VERSION 5.8 ;
BUSBITCHARS "[]" ;
DIVIDERCHAR "/" ;
UNITS
    DATABASE MICRONS 1000 ;
END UNITS

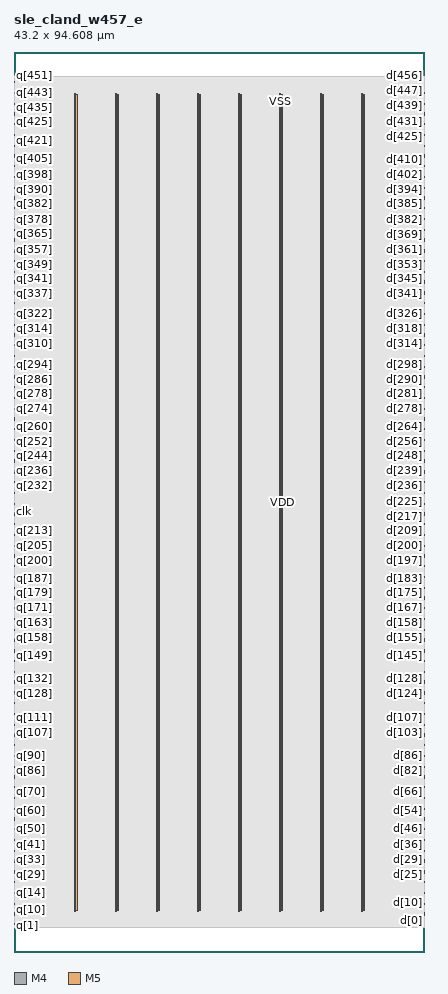
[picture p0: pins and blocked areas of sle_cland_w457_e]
MACRO sle_cland_w457_e
  FOREIGN sle_cland_w457_e 0 0 ;
  CLASS BLOCK ;
  SIZE 43.2 BY 94.608 ;
  PIN clk
    DIRECTION INPUT ;
    USE SIGNAL ;
    PORT
      LAYER M4 ;
        RECT  0 46.32 0.084 46.344 ;
    END
  END clk
  PIN d[0]
    DIRECTION INPUT ;
    USE SIGNAL ;
    PORT
      LAYER M4 ;
        RECT  43.116 3.312 43.2 3.336 ;
    END
  END d[0]
  PIN d[100]
    DIRECTION INPUT ;
    USE SIGNAL ;
    PORT
      LAYER M4 ;
        RECT  43.116 22.512 43.2 22.536 ;
    END
  END d[100]
  PIN d[101]
    DIRECTION INPUT ;
    USE SIGNAL ;
    PORT
      LAYER M4 ;
        RECT  43.116 22.704 43.2 22.728 ;
    END
  END d[101]
  PIN d[102]
    DIRECTION INPUT ;
    USE SIGNAL ;
    PORT
      LAYER M4 ;
        RECT  43.116 22.896 43.2 22.92 ;
    END
  END d[102]
  PIN d[103]
    DIRECTION INPUT ;
    USE SIGNAL ;
    PORT
      LAYER M4 ;
        RECT  43.116 23.088 43.2 23.112 ;
    END
  END d[103]
  PIN d[104]
    DIRECTION INPUT ;
    USE SIGNAL ;
    PORT
      LAYER M4 ;
        RECT  43.116 23.28 43.2 23.304 ;
    END
  END d[104]
  PIN d[105]
    DIRECTION INPUT ;
    USE SIGNAL ;
    PORT
      LAYER M4 ;
        RECT  43.116 23.472 43.2 23.496 ;
    END
  END d[105]
  PIN d[106]
    DIRECTION INPUT ;
    USE SIGNAL ;
    PORT
      LAYER M4 ;
        RECT  43.116 23.664 43.2 23.688 ;
    END
  END d[106]
  PIN d[107]
    DIRECTION INPUT ;
    USE SIGNAL ;
    PORT
      LAYER M4 ;
        RECT  43.116 23.856 43.2 23.88 ;
    END
  END d[107]
  PIN d[108]
    DIRECTION INPUT ;
    USE SIGNAL ;
    PORT
      LAYER M4 ;
        RECT  43.116 24.048 43.2 24.072 ;
    END
  END d[108]
  PIN d[109]
    DIRECTION INPUT ;
    USE SIGNAL ;
    PORT
      LAYER M4 ;
        RECT  43.116 24.24 43.2 24.264 ;
    END
  END d[109]
  PIN d[10]
    DIRECTION INPUT ;
    USE SIGNAL ;
    PORT
      LAYER M4 ;
        RECT  43.116 5.232 43.2 5.256 ;
    END
  END d[10]
  PIN d[110]
    DIRECTION INPUT ;
    USE SIGNAL ;
    PORT
      LAYER M4 ;
        RECT  43.116 24.432 43.2 24.456 ;
    END
  END d[110]
  PIN d[111]
    DIRECTION INPUT ;
    USE SIGNAL ;
    PORT
      LAYER M4 ;
        RECT  43.116 24.624 43.2 24.648 ;
    END
  END d[111]
  PIN d[112]
    DIRECTION INPUT ;
    USE SIGNAL ;
    PORT
      LAYER M4 ;
        RECT  43.116 24.816 43.2 24.84 ;
    END
  END d[112]
  PIN d[113]
    DIRECTION INPUT ;
    USE SIGNAL ;
    PORT
      LAYER M4 ;
        RECT  43.116 25.008 43.2 25.032 ;
    END
  END d[113]
  PIN d[114]
    DIRECTION INPUT ;
    USE SIGNAL ;
    PORT
      LAYER M4 ;
        RECT  43.116 25.2 43.2 25.224 ;
    END
  END d[114]
  PIN d[115]
    DIRECTION INPUT ;
    USE SIGNAL ;
    PORT
      LAYER M4 ;
        RECT  43.116 25.584 43.2 25.608 ;
    END
  END d[115]
  PIN d[116]
    DIRECTION INPUT ;
    USE SIGNAL ;
    PORT
      LAYER M4 ;
        RECT  43.116 25.392 43.2 25.416 ;
    END
  END d[116]
  PIN d[117]
    DIRECTION INPUT ;
    USE SIGNAL ;
    PORT
      LAYER M4 ;
        RECT  43.116 25.776 43.2 25.8 ;
    END
  END d[117]
  PIN d[118]
    DIRECTION INPUT ;
    USE SIGNAL ;
    PORT
      LAYER M4 ;
        RECT  43.116 26.16 43.2 26.184 ;
    END
  END d[118]
  PIN d[119]
    DIRECTION INPUT ;
    USE SIGNAL ;
    PORT
      LAYER M4 ;
        RECT  43.116 25.968 43.2 25.992 ;
    END
  END d[119]
  PIN d[11]
    DIRECTION INPUT ;
    USE SIGNAL ;
    PORT
      LAYER M4 ;
        RECT  43.116 5.424 43.2 5.448 ;
    END
  END d[11]
  PIN d[120]
    DIRECTION INPUT ;
    USE SIGNAL ;
    PORT
      LAYER M4 ;
        RECT  43.116 26.352 43.2 26.376 ;
    END
  END d[120]
  PIN d[121]
    DIRECTION INPUT ;
    USE SIGNAL ;
    PORT
      LAYER M4 ;
        RECT  43.116 26.544 43.2 26.568 ;
    END
  END d[121]
  PIN d[122]
    DIRECTION INPUT ;
    USE SIGNAL ;
    PORT
      LAYER M4 ;
        RECT  43.116 26.736 43.2 26.76 ;
    END
  END d[122]
  PIN d[123]
    DIRECTION INPUT ;
    USE SIGNAL ;
    PORT
      LAYER M4 ;
        RECT  43.116 26.928 43.2 26.952 ;
    END
  END d[123]
  PIN d[124]
    DIRECTION INPUT ;
    USE SIGNAL ;
    PORT
      LAYER M4 ;
        RECT  43.116 27.12 43.2 27.144 ;
    END
  END d[124]
  PIN d[125]
    DIRECTION INPUT ;
    USE SIGNAL ;
    PORT
      LAYER M4 ;
        RECT  43.116 27.312 43.2 27.336 ;
    END
  END d[125]
  PIN d[126]
    DIRECTION INPUT ;
    USE SIGNAL ;
    PORT
      LAYER M4 ;
        RECT  43.116 27.504 43.2 27.528 ;
    END
  END d[126]
  PIN d[127]
    DIRECTION INPUT ;
    USE SIGNAL ;
    PORT
      LAYER M4 ;
        RECT  43.116 27.696 43.2 27.72 ;
    END
  END d[127]
  PIN d[128]
    DIRECTION INPUT ;
    USE SIGNAL ;
    PORT
      LAYER M4 ;
        RECT  43.116 27.888 43.2 27.912 ;
    END
  END d[128]
  PIN d[129]
    DIRECTION INPUT ;
    USE SIGNAL ;
    PORT
      LAYER M4 ;
        RECT  43.116 28.08 43.2 28.104 ;
    END
  END d[129]
  PIN d[12]
    DIRECTION INPUT ;
    USE SIGNAL ;
    PORT
      LAYER M4 ;
        RECT  43.116 5.616 43.2 5.64 ;
    END
  END d[12]
  PIN d[130]
    DIRECTION INPUT ;
    USE SIGNAL ;
    PORT
      LAYER M4 ;
        RECT  43.116 28.272 43.2 28.296 ;
    END
  END d[130]
  PIN d[131]
    DIRECTION INPUT ;
    USE SIGNAL ;
    PORT
      LAYER M4 ;
        RECT  43.116 28.464 43.2 28.488 ;
    END
  END d[131]
  PIN d[132]
    DIRECTION INPUT ;
    USE SIGNAL ;
    PORT
      LAYER M4 ;
        RECT  43.116 28.656 43.2 28.68 ;
    END
  END d[132]
  PIN d[133]
    DIRECTION INPUT ;
    USE SIGNAL ;
    PORT
      LAYER M4 ;
        RECT  43.116 28.848 43.2 28.872 ;
    END
  END d[133]
  PIN d[134]
    DIRECTION INPUT ;
    USE SIGNAL ;
    PORT
      LAYER M4 ;
        RECT  43.116 29.04 43.2 29.064 ;
    END
  END d[134]
  PIN d[135]
    DIRECTION INPUT ;
    USE SIGNAL ;
    PORT
      LAYER M4 ;
        RECT  43.116 29.232 43.2 29.256 ;
    END
  END d[135]
  PIN d[136]
    DIRECTION INPUT ;
    USE SIGNAL ;
    PORT
      LAYER M4 ;
        RECT  43.116 29.424 43.2 29.448 ;
    END
  END d[136]
  PIN d[137]
    DIRECTION INPUT ;
    USE SIGNAL ;
    PORT
      LAYER M4 ;
        RECT  43.116 29.616 43.2 29.64 ;
    END
  END d[137]
  PIN d[138]
    DIRECTION INPUT ;
    USE SIGNAL ;
    PORT
      LAYER M4 ;
        RECT  43.116 30 43.2 30.024 ;
    END
  END d[138]
  PIN d[139]
    DIRECTION INPUT ;
    USE SIGNAL ;
    PORT
      LAYER M4 ;
        RECT  43.116 29.808 43.2 29.832 ;
    END
  END d[139]
  PIN d[13]
    DIRECTION INPUT ;
    USE SIGNAL ;
    PORT
      LAYER M4 ;
        RECT  43.116 5.808 43.2 5.832 ;
    END
  END d[13]
  PIN d[140]
    DIRECTION INPUT ;
    USE SIGNAL ;
    PORT
      LAYER M4 ;
        RECT  43.116 30.192 43.2 30.216 ;
    END
  END d[140]
  PIN d[141]
    DIRECTION INPUT ;
    USE SIGNAL ;
    PORT
      LAYER M4 ;
        RECT  43.116 30.384 43.2 30.408 ;
    END
  END d[141]
  PIN d[142]
    DIRECTION INPUT ;
    USE SIGNAL ;
    PORT
      LAYER M4 ;
        RECT  43.116 30.576 43.2 30.6 ;
    END
  END d[142]
  PIN d[143]
    DIRECTION INPUT ;
    USE SIGNAL ;
    PORT
      LAYER M4 ;
        RECT  43.116 30.768 43.2 30.792 ;
    END
  END d[143]
  PIN d[144]
    DIRECTION INPUT ;
    USE SIGNAL ;
    PORT
      LAYER M4 ;
        RECT  43.116 30.96 43.2 30.984 ;
    END
  END d[144]
  PIN d[145]
    DIRECTION INPUT ;
    USE SIGNAL ;
    PORT
      LAYER M4 ;
        RECT  43.116 31.152 43.2 31.176 ;
    END
  END d[145]
  PIN d[146]
    DIRECTION INPUT ;
    USE SIGNAL ;
    PORT
      LAYER M4 ;
        RECT  43.116 31.344 43.2 31.368 ;
    END
  END d[146]
  PIN d[147]
    DIRECTION INPUT ;
    USE SIGNAL ;
    PORT
      LAYER M4 ;
        RECT  43.116 31.536 43.2 31.56 ;
    END
  END d[147]
  PIN d[148]
    DIRECTION INPUT ;
    USE SIGNAL ;
    PORT
      LAYER M4 ;
        RECT  43.116 31.728 43.2 31.752 ;
    END
  END d[148]
  PIN d[149]
    DIRECTION INPUT ;
    USE SIGNAL ;
    PORT
      LAYER M4 ;
        RECT  43.116 31.92 43.2 31.944 ;
    END
  END d[149]
  PIN d[14]
    DIRECTION INPUT ;
    USE SIGNAL ;
    PORT
      LAYER M4 ;
        RECT  43.116 6.192 43.2 6.216 ;
    END
  END d[14]
  PIN d[150]
    DIRECTION INPUT ;
    USE SIGNAL ;
    PORT
      LAYER M4 ;
        RECT  43.116 32.112 43.2 32.136 ;
    END
  END d[150]
  PIN d[151]
    DIRECTION INPUT ;
    USE SIGNAL ;
    PORT
      LAYER M4 ;
        RECT  43.116 32.304 43.2 32.328 ;
    END
  END d[151]
  PIN d[152]
    DIRECTION INPUT ;
    USE SIGNAL ;
    PORT
      LAYER M4 ;
        RECT  43.116 32.496 43.2 32.52 ;
    END
  END d[152]
  PIN d[153]
    DIRECTION INPUT ;
    USE SIGNAL ;
    PORT
      LAYER M4 ;
        RECT  43.116 32.688 43.2 32.712 ;
    END
  END d[153]
  PIN d[154]
    DIRECTION INPUT ;
    USE SIGNAL ;
    PORT
      LAYER M4 ;
        RECT  43.116 32.88 43.2 32.904 ;
    END
  END d[154]
  PIN d[155]
    DIRECTION INPUT ;
    USE SIGNAL ;
    PORT
      LAYER M4 ;
        RECT  43.116 33.072 43.2 33.096 ;
    END
  END d[155]
  PIN d[156]
    DIRECTION INPUT ;
    USE SIGNAL ;
    PORT
      LAYER M4 ;
        RECT  43.116 33.264 43.2 33.288 ;
    END
  END d[156]
  PIN d[157]
    DIRECTION INPUT ;
    USE SIGNAL ;
    PORT
      LAYER M4 ;
        RECT  43.116 33.456 43.2 33.48 ;
    END
  END d[157]
  PIN d[158]
    DIRECTION INPUT ;
    USE SIGNAL ;
    PORT
      LAYER M4 ;
        RECT  43.116 33.84 43.2 33.864 ;
    END
  END d[158]
  PIN d[159]
    DIRECTION INPUT ;
    USE SIGNAL ;
    PORT
      LAYER M4 ;
        RECT  43.116 33.648 43.2 33.672 ;
    END
  END d[159]
  PIN d[15]
    DIRECTION INPUT ;
    USE SIGNAL ;
    PORT
      LAYER M4 ;
        RECT  43.116 6 43.2 6.024 ;
    END
  END d[15]
  PIN d[160]
    DIRECTION INPUT ;
    USE SIGNAL ;
    PORT
      LAYER M4 ;
        RECT  43.116 34.224 43.2 34.248 ;
    END
  END d[160]
  PIN d[161]
    DIRECTION INPUT ;
    USE SIGNAL ;
    PORT
      LAYER M4 ;
        RECT  43.116 34.032 43.2 34.056 ;
    END
  END d[161]
  PIN d[162]
    DIRECTION INPUT ;
    USE SIGNAL ;
    PORT
      LAYER M4 ;
        RECT  43.116 34.416 43.2 34.44 ;
    END
  END d[162]
  PIN d[163]
    DIRECTION INPUT ;
    USE SIGNAL ;
    PORT
      LAYER M4 ;
        RECT  43.116 34.608 43.2 34.632 ;
    END
  END d[163]
  PIN d[164]
    DIRECTION INPUT ;
    USE SIGNAL ;
    PORT
      LAYER M4 ;
        RECT  43.116 34.8 43.2 34.824 ;
    END
  END d[164]
  PIN d[165]
    DIRECTION INPUT ;
    USE SIGNAL ;
    PORT
      LAYER M4 ;
        RECT  43.116 34.992 43.2 35.016 ;
    END
  END d[165]
  PIN d[166]
    DIRECTION INPUT ;
    USE SIGNAL ;
    PORT
      LAYER M4 ;
        RECT  43.116 35.184 43.2 35.208 ;
    END
  END d[166]
  PIN d[167]
    DIRECTION INPUT ;
    USE SIGNAL ;
    PORT
      LAYER M4 ;
        RECT  43.116 35.376 43.2 35.4 ;
    END
  END d[167]
  PIN d[168]
    DIRECTION INPUT ;
    USE SIGNAL ;
    PORT
      LAYER M4 ;
        RECT  43.116 35.568 43.2 35.592 ;
    END
  END d[168]
  PIN d[169]
    DIRECTION INPUT ;
    USE SIGNAL ;
    PORT
      LAYER M4 ;
        RECT  43.116 35.76 43.2 35.784 ;
    END
  END d[169]
  PIN d[16]
    DIRECTION INPUT ;
    USE SIGNAL ;
    PORT
      LAYER M4 ;
        RECT  43.116 6.384 43.2 6.408 ;
    END
  END d[16]
  PIN d[170]
    DIRECTION INPUT ;
    USE SIGNAL ;
    PORT
      LAYER M4 ;
        RECT  43.116 35.952 43.2 35.976 ;
    END
  END d[170]
  PIN d[171]
    DIRECTION INPUT ;
    USE SIGNAL ;
    PORT
      LAYER M4 ;
        RECT  43.116 36.144 43.2 36.168 ;
    END
  END d[171]
  PIN d[172]
    DIRECTION INPUT ;
    USE SIGNAL ;
    PORT
      LAYER M4 ;
        RECT  43.116 36.336 43.2 36.36 ;
    END
  END d[172]
  PIN d[173]
    DIRECTION INPUT ;
    USE SIGNAL ;
    PORT
      LAYER M4 ;
        RECT  43.116 36.528 43.2 36.552 ;
    END
  END d[173]
  PIN d[174]
    DIRECTION INPUT ;
    USE SIGNAL ;
    PORT
      LAYER M4 ;
        RECT  43.116 36.72 43.2 36.744 ;
    END
  END d[174]
  PIN d[175]
    DIRECTION INPUT ;
    USE SIGNAL ;
    PORT
      LAYER M4 ;
        RECT  43.116 36.912 43.2 36.936 ;
    END
  END d[175]
  PIN d[176]
    DIRECTION INPUT ;
    USE SIGNAL ;
    PORT
      LAYER M4 ;
        RECT  43.116 37.104 43.2 37.128 ;
    END
  END d[176]
  PIN d[177]
    DIRECTION INPUT ;
    USE SIGNAL ;
    PORT
      LAYER M4 ;
        RECT  43.116 37.488 43.2 37.512 ;
    END
  END d[177]
  PIN d[178]
    DIRECTION INPUT ;
    USE SIGNAL ;
    PORT
      LAYER M4 ;
        RECT  43.116 37.296 43.2 37.32 ;
    END
  END d[178]
  PIN d[179]
    DIRECTION INPUT ;
    USE SIGNAL ;
    PORT
      LAYER M4 ;
        RECT  43.116 37.68 43.2 37.704 ;
    END
  END d[179]
  PIN d[17]
    DIRECTION INPUT ;
    USE SIGNAL ;
    PORT
      LAYER M4 ;
        RECT  43.116 6.576 43.2 6.6 ;
    END
  END d[17]
  PIN d[180]
    DIRECTION INPUT ;
    USE SIGNAL ;
    PORT
      LAYER M4 ;
        RECT  43.116 38.064 43.2 38.088 ;
    END
  END d[180]
  PIN d[181]
    DIRECTION INPUT ;
    USE SIGNAL ;
    PORT
      LAYER M4 ;
        RECT  43.116 37.872 43.2 37.896 ;
    END
  END d[181]
  PIN d[182]
    DIRECTION INPUT ;
    USE SIGNAL ;
    PORT
      LAYER M4 ;
        RECT  43.116 38.256 43.2 38.28 ;
    END
  END d[182]
  PIN d[183]
    DIRECTION INPUT ;
    USE SIGNAL ;
    PORT
      LAYER M4 ;
        RECT  43.116 38.448 43.2 38.472 ;
    END
  END d[183]
  PIN d[184]
    DIRECTION INPUT ;
    USE SIGNAL ;
    PORT
      LAYER M4 ;
        RECT  43.116 38.64 43.2 38.664 ;
    END
  END d[184]
  PIN d[185]
    DIRECTION INPUT ;
    USE SIGNAL ;
    PORT
      LAYER M4 ;
        RECT  43.116 38.832 43.2 38.856 ;
    END
  END d[185]
  PIN d[186]
    DIRECTION INPUT ;
    USE SIGNAL ;
    PORT
      LAYER M4 ;
        RECT  43.116 39.024 43.2 39.048 ;
    END
  END d[186]
  PIN d[187]
    DIRECTION INPUT ;
    USE SIGNAL ;
    PORT
      LAYER M4 ;
        RECT  43.116 39.216 43.2 39.24 ;
    END
  END d[187]
  PIN d[188]
    DIRECTION INPUT ;
    USE SIGNAL ;
    PORT
      LAYER M4 ;
        RECT  43.116 39.408 43.2 39.432 ;
    END
  END d[188]
  PIN d[189]
    DIRECTION INPUT ;
    USE SIGNAL ;
    PORT
      LAYER M4 ;
        RECT  43.116 39.6 43.2 39.624 ;
    END
  END d[189]
  PIN d[18]
    DIRECTION INPUT ;
    USE SIGNAL ;
    PORT
      LAYER M4 ;
        RECT  43.116 6.768 43.2 6.792 ;
    END
  END d[18]
  PIN d[190]
    DIRECTION INPUT ;
    USE SIGNAL ;
    PORT
      LAYER M4 ;
        RECT  43.116 39.792 43.2 39.816 ;
    END
  END d[190]
  PIN d[191]
    DIRECTION INPUT ;
    USE SIGNAL ;
    PORT
      LAYER M4 ;
        RECT  43.116 39.984 43.2 40.008 ;
    END
  END d[191]
  PIN d[192]
    DIRECTION INPUT ;
    USE SIGNAL ;
    PORT
      LAYER M4 ;
        RECT  43.116 40.176 43.2 40.2 ;
    END
  END d[192]
  PIN d[193]
    DIRECTION INPUT ;
    USE SIGNAL ;
    PORT
      LAYER M4 ;
        RECT  43.116 40.368 43.2 40.392 ;
    END
  END d[193]
  PIN d[194]
    DIRECTION INPUT ;
    USE SIGNAL ;
    PORT
      LAYER M4 ;
        RECT  43.116 40.56 43.2 40.584 ;
    END
  END d[194]
  PIN d[195]
    DIRECTION INPUT ;
    USE SIGNAL ;
    PORT
      LAYER M4 ;
        RECT  43.116 40.752 43.2 40.776 ;
    END
  END d[195]
  PIN d[196]
    DIRECTION INPUT ;
    USE SIGNAL ;
    PORT
      LAYER M4 ;
        RECT  43.116 40.944 43.2 40.968 ;
    END
  END d[196]
  PIN d[197]
    DIRECTION INPUT ;
    USE SIGNAL ;
    PORT
      LAYER M4 ;
        RECT  43.116 41.136 43.2 41.16 ;
    END
  END d[197]
  PIN d[198]
    DIRECTION INPUT ;
    USE SIGNAL ;
    PORT
      LAYER M4 ;
        RECT  43.116 41.328 43.2 41.352 ;
    END
  END d[198]
  PIN d[199]
    DIRECTION INPUT ;
    USE SIGNAL ;
    PORT
      LAYER M4 ;
        RECT  43.116 41.52 43.2 41.544 ;
    END
  END d[199]
  PIN d[19]
    DIRECTION INPUT ;
    USE SIGNAL ;
    PORT
      LAYER M4 ;
        RECT  43.116 6.96 43.2 6.984 ;
    END
  END d[19]
  PIN d[1]
    DIRECTION INPUT ;
    USE SIGNAL ;
    PORT
      LAYER M4 ;
        RECT  43.116 3.504 43.2 3.528 ;
    END
  END d[1]
  PIN d[200]
    DIRECTION INPUT ;
    USE SIGNAL ;
    PORT
      LAYER M4 ;
        RECT  43.116 41.904 43.2 41.928 ;
    END
  END d[200]
  PIN d[201]
    DIRECTION INPUT ;
    USE SIGNAL ;
    PORT
      LAYER M4 ;
        RECT  43.116 41.712 43.2 41.736 ;
    END
  END d[201]
  PIN d[202]
    DIRECTION INPUT ;
    USE SIGNAL ;
    PORT
      LAYER M4 ;
        RECT  43.116 42.096 43.2 42.12 ;
    END
  END d[202]
  PIN d[203]
    DIRECTION INPUT ;
    USE SIGNAL ;
    PORT
      LAYER M4 ;
        RECT  43.116 42.288 43.2 42.312 ;
    END
  END d[203]
  PIN d[204]
    DIRECTION INPUT ;
    USE SIGNAL ;
    PORT
      LAYER M4 ;
        RECT  43.116 42.48 43.2 42.504 ;
    END
  END d[204]
  PIN d[205]
    DIRECTION INPUT ;
    USE SIGNAL ;
    PORT
      LAYER M4 ;
        RECT  43.116 42.672 43.2 42.696 ;
    END
  END d[205]
  PIN d[206]
    DIRECTION INPUT ;
    USE SIGNAL ;
    PORT
      LAYER M4 ;
        RECT  43.116 42.864 43.2 42.888 ;
    END
  END d[206]
  PIN d[207]
    DIRECTION INPUT ;
    USE SIGNAL ;
    PORT
      LAYER M4 ;
        RECT  43.116 43.056 43.2 43.08 ;
    END
  END d[207]
  PIN d[208]
    DIRECTION INPUT ;
    USE SIGNAL ;
    PORT
      LAYER M4 ;
        RECT  43.116 43.248 43.2 43.272 ;
    END
  END d[208]
  PIN d[209]
    DIRECTION INPUT ;
    USE SIGNAL ;
    PORT
      LAYER M4 ;
        RECT  43.116 43.44 43.2 43.464 ;
    END
  END d[209]
  PIN d[20]
    DIRECTION INPUT ;
    USE SIGNAL ;
    PORT
      LAYER M4 ;
        RECT  43.116 7.152 43.2 7.176 ;
    END
  END d[20]
  PIN d[210]
    DIRECTION INPUT ;
    USE SIGNAL ;
    PORT
      LAYER M4 ;
        RECT  43.116 43.632 43.2 43.656 ;
    END
  END d[210]
  PIN d[211]
    DIRECTION INPUT ;
    USE SIGNAL ;
    PORT
      LAYER M4 ;
        RECT  43.116 43.824 43.2 43.848 ;
    END
  END d[211]
  PIN d[212]
    DIRECTION INPUT ;
    USE SIGNAL ;
    PORT
      LAYER M4 ;
        RECT  43.116 44.016 43.2 44.04 ;
    END
  END d[212]
  PIN d[213]
    DIRECTION INPUT ;
    USE SIGNAL ;
    PORT
      LAYER M4 ;
        RECT  43.116 44.208 43.2 44.232 ;
    END
  END d[213]
  PIN d[214]
    DIRECTION INPUT ;
    USE SIGNAL ;
    PORT
      LAYER M4 ;
        RECT  43.116 44.4 43.2 44.424 ;
    END
  END d[214]
  PIN d[215]
    DIRECTION INPUT ;
    USE SIGNAL ;
    PORT
      LAYER M4 ;
        RECT  43.116 44.592 43.2 44.616 ;
    END
  END d[215]
  PIN d[216]
    DIRECTION INPUT ;
    USE SIGNAL ;
    PORT
      LAYER M4 ;
        RECT  43.116 44.784 43.2 44.808 ;
    END
  END d[216]
  PIN d[217]
    DIRECTION INPUT ;
    USE SIGNAL ;
    PORT
      LAYER M4 ;
        RECT  43.116 44.976 43.2 45 ;
    END
  END d[217]
  PIN d[218]
    DIRECTION INPUT ;
    USE SIGNAL ;
    PORT
      LAYER M4 ;
        RECT  43.116 45.168 43.2 45.192 ;
    END
  END d[218]
  PIN d[219]
    DIRECTION INPUT ;
    USE SIGNAL ;
    PORT
      LAYER M4 ;
        RECT  43.116 45.36 43.2 45.384 ;
    END
  END d[219]
  PIN d[21]
    DIRECTION INPUT ;
    USE SIGNAL ;
    PORT
      LAYER M4 ;
        RECT  43.116 7.344 43.2 7.368 ;
    END
  END d[21]
  PIN d[220]
    DIRECTION INPUT ;
    USE SIGNAL ;
    PORT
      LAYER M4 ;
        RECT  43.116 45.744 43.2 45.768 ;
    END
  END d[220]
  PIN d[221]
    DIRECTION INPUT ;
    USE SIGNAL ;
    PORT
      LAYER M4 ;
        RECT  43.116 45.552 43.2 45.576 ;
    END
  END d[221]
  PIN d[222]
    DIRECTION INPUT ;
    USE SIGNAL ;
    PORT
      LAYER M4 ;
        RECT  43.116 46.128 43.2 46.152 ;
    END
  END d[222]
  PIN d[223]
    DIRECTION INPUT ;
    USE SIGNAL ;
    PORT
      LAYER M4 ;
        RECT  43.116 45.936 43.2 45.96 ;
    END
  END d[223]
  PIN d[224]
    DIRECTION INPUT ;
    USE SIGNAL ;
    PORT
      LAYER M4 ;
        RECT  43.116 46.32 43.2 46.344 ;
    END
  END d[224]
  PIN d[225]
    DIRECTION INPUT ;
    USE SIGNAL ;
    PORT
      LAYER M4 ;
        RECT  43.116 46.512 43.2 46.536 ;
    END
  END d[225]
  PIN d[226]
    DIRECTION INPUT ;
    USE SIGNAL ;
    PORT
      LAYER M4 ;
        RECT  43.116 46.704 43.2 46.728 ;
    END
  END d[226]
  PIN d[227]
    DIRECTION INPUT ;
    USE SIGNAL ;
    PORT
      LAYER M4 ;
        RECT  43.116 46.896 43.2 46.92 ;
    END
  END d[227]
  PIN d[228]
    DIRECTION INPUT ;
    USE SIGNAL ;
    PORT
      LAYER M4 ;
        RECT  43.116 47.472 43.2 47.496 ;
    END
  END d[228]
  PIN d[229]
    DIRECTION INPUT ;
    USE SIGNAL ;
    PORT
      LAYER M4 ;
        RECT  43.116 47.664 43.2 47.688 ;
    END
  END d[229]
  PIN d[22]
    DIRECTION INPUT ;
    USE SIGNAL ;
    PORT
      LAYER M4 ;
        RECT  43.116 7.536 43.2 7.56 ;
    END
  END d[22]
  PIN d[230]
    DIRECTION INPUT ;
    USE SIGNAL ;
    PORT
      LAYER M4 ;
        RECT  43.116 47.856 43.2 47.88 ;
    END
  END d[230]
  PIN d[231]
    DIRECTION INPUT ;
    USE SIGNAL ;
    PORT
      LAYER M4 ;
        RECT  43.116 48.048 43.2 48.072 ;
    END
  END d[231]
  PIN d[232]
    DIRECTION INPUT ;
    USE SIGNAL ;
    PORT
      LAYER M4 ;
        RECT  43.116 48.24 43.2 48.264 ;
    END
  END d[232]
  PIN d[233]
    DIRECTION INPUT ;
    USE SIGNAL ;
    PORT
      LAYER M4 ;
        RECT  43.116 48.432 43.2 48.456 ;
    END
  END d[233]
  PIN d[234]
    DIRECTION INPUT ;
    USE SIGNAL ;
    PORT
      LAYER M4 ;
        RECT  43.116 48.624 43.2 48.648 ;
    END
  END d[234]
  PIN d[235]
    DIRECTION INPUT ;
    USE SIGNAL ;
    PORT
      LAYER M4 ;
        RECT  43.116 48.816 43.2 48.84 ;
    END
  END d[235]
  PIN d[236]
    DIRECTION INPUT ;
    USE SIGNAL ;
    PORT
      LAYER M4 ;
        RECT  43.116 49.008 43.2 49.032 ;
    END
  END d[236]
  PIN d[237]
    DIRECTION INPUT ;
    USE SIGNAL ;
    PORT
      LAYER M4 ;
        RECT  43.116 49.2 43.2 49.224 ;
    END
  END d[237]
  PIN d[238]
    DIRECTION INPUT ;
    USE SIGNAL ;
    PORT
      LAYER M4 ;
        RECT  43.116 49.392 43.2 49.416 ;
    END
  END d[238]
  PIN d[239]
    DIRECTION INPUT ;
    USE SIGNAL ;
    PORT
      LAYER M4 ;
        RECT  43.116 49.776 43.2 49.8 ;
    END
  END d[239]
  PIN d[23]
    DIRECTION INPUT ;
    USE SIGNAL ;
    PORT
      LAYER M4 ;
        RECT  43.116 7.728 43.2 7.752 ;
    END
  END d[23]
  PIN d[240]
    DIRECTION INPUT ;
    USE SIGNAL ;
    PORT
      LAYER M4 ;
        RECT  43.116 49.584 43.2 49.608 ;
    END
  END d[240]
  PIN d[241]
    DIRECTION INPUT ;
    USE SIGNAL ;
    PORT
      LAYER M4 ;
        RECT  43.116 49.968 43.2 49.992 ;
    END
  END d[241]
  PIN d[242]
    DIRECTION INPUT ;
    USE SIGNAL ;
    PORT
      LAYER M4 ;
        RECT  43.116 50.352 43.2 50.376 ;
    END
  END d[242]
  PIN d[243]
    DIRECTION INPUT ;
    USE SIGNAL ;
    PORT
      LAYER M4 ;
        RECT  43.116 50.16 43.2 50.184 ;
    END
  END d[243]
  PIN d[244]
    DIRECTION INPUT ;
    USE SIGNAL ;
    PORT
      LAYER M4 ;
        RECT  43.116 50.544 43.2 50.568 ;
    END
  END d[244]
  PIN d[245]
    DIRECTION INPUT ;
    USE SIGNAL ;
    PORT
      LAYER M4 ;
        RECT  43.116 50.736 43.2 50.76 ;
    END
  END d[245]
  PIN d[246]
    DIRECTION INPUT ;
    USE SIGNAL ;
    PORT
      LAYER M4 ;
        RECT  43.116 50.928 43.2 50.952 ;
    END
  END d[246]
  PIN d[247]
    DIRECTION INPUT ;
    USE SIGNAL ;
    PORT
      LAYER M4 ;
        RECT  43.116 51.12 43.2 51.144 ;
    END
  END d[247]
  PIN d[248]
    DIRECTION INPUT ;
    USE SIGNAL ;
    PORT
      LAYER M4 ;
        RECT  43.116 51.312 43.2 51.336 ;
    END
  END d[248]
  PIN d[249]
    DIRECTION INPUT ;
    USE SIGNAL ;
    PORT
      LAYER M4 ;
        RECT  43.116 51.504 43.2 51.528 ;
    END
  END d[249]
  PIN d[24]
    DIRECTION INPUT ;
    USE SIGNAL ;
    PORT
      LAYER M4 ;
        RECT  43.116 7.92 43.2 7.944 ;
    END
  END d[24]
  PIN d[250]
    DIRECTION INPUT ;
    USE SIGNAL ;
    PORT
      LAYER M4 ;
        RECT  43.116 51.696 43.2 51.72 ;
    END
  END d[250]
  PIN d[251]
    DIRECTION INPUT ;
    USE SIGNAL ;
    PORT
      LAYER M4 ;
        RECT  43.116 51.888 43.2 51.912 ;
    END
  END d[251]
  PIN d[252]
    DIRECTION INPUT ;
    USE SIGNAL ;
    PORT
      LAYER M4 ;
        RECT  43.116 52.08 43.2 52.104 ;
    END
  END d[252]
  PIN d[253]
    DIRECTION INPUT ;
    USE SIGNAL ;
    PORT
      LAYER M4 ;
        RECT  43.116 52.272 43.2 52.296 ;
    END
  END d[253]
  PIN d[254]
    DIRECTION INPUT ;
    USE SIGNAL ;
    PORT
      LAYER M4 ;
        RECT  43.116 52.464 43.2 52.488 ;
    END
  END d[254]
  PIN d[255]
    DIRECTION INPUT ;
    USE SIGNAL ;
    PORT
      LAYER M4 ;
        RECT  43.116 52.656 43.2 52.68 ;
    END
  END d[255]
  PIN d[256]
    DIRECTION INPUT ;
    USE SIGNAL ;
    PORT
      LAYER M4 ;
        RECT  43.116 52.848 43.2 52.872 ;
    END
  END d[256]
  PIN d[257]
    DIRECTION INPUT ;
    USE SIGNAL ;
    PORT
      LAYER M4 ;
        RECT  43.116 53.04 43.2 53.064 ;
    END
  END d[257]
  PIN d[258]
    DIRECTION INPUT ;
    USE SIGNAL ;
    PORT
      LAYER M4 ;
        RECT  43.116 53.232 43.2 53.256 ;
    END
  END d[258]
  PIN d[259]
    DIRECTION INPUT ;
    USE SIGNAL ;
    PORT
      LAYER M4 ;
        RECT  43.116 53.424 43.2 53.448 ;
    END
  END d[259]
  PIN d[25]
    DIRECTION INPUT ;
    USE SIGNAL ;
    PORT
      LAYER M4 ;
        RECT  43.116 8.112 43.2 8.136 ;
    END
  END d[25]
  PIN d[260]
    DIRECTION INPUT ;
    USE SIGNAL ;
    PORT
      LAYER M4 ;
        RECT  43.116 53.616 43.2 53.64 ;
    END
  END d[260]
  PIN d[261]
    DIRECTION INPUT ;
    USE SIGNAL ;
    PORT
      LAYER M4 ;
        RECT  43.116 54 43.2 54.024 ;
    END
  END d[261]
  PIN d[262]
    DIRECTION INPUT ;
    USE SIGNAL ;
    PORT
      LAYER M4 ;
        RECT  43.116 53.808 43.2 53.832 ;
    END
  END d[262]
  PIN d[263]
    DIRECTION INPUT ;
    USE SIGNAL ;
    PORT
      LAYER M4 ;
        RECT  43.116 54.192 43.2 54.216 ;
    END
  END d[263]
  PIN d[264]
    DIRECTION INPUT ;
    USE SIGNAL ;
    PORT
      LAYER M4 ;
        RECT  43.116 54.384 43.2 54.408 ;
    END
  END d[264]
  PIN d[265]
    DIRECTION INPUT ;
    USE SIGNAL ;
    PORT
      LAYER M4 ;
        RECT  43.116 54.576 43.2 54.6 ;
    END
  END d[265]
  PIN d[266]
    DIRECTION INPUT ;
    USE SIGNAL ;
    PORT
      LAYER M4 ;
        RECT  43.116 54.768 43.2 54.792 ;
    END
  END d[266]
  PIN d[267]
    DIRECTION INPUT ;
    USE SIGNAL ;
    PORT
      LAYER M4 ;
        RECT  43.116 54.96 43.2 54.984 ;
    END
  END d[267]
  PIN d[268]
    DIRECTION INPUT ;
    USE SIGNAL ;
    PORT
      LAYER M4 ;
        RECT  43.116 55.152 43.2 55.176 ;
    END
  END d[268]
  PIN d[269]
    DIRECTION INPUT ;
    USE SIGNAL ;
    PORT
      LAYER M4 ;
        RECT  43.116 55.344 43.2 55.368 ;
    END
  END d[269]
  PIN d[26]
    DIRECTION INPUT ;
    USE SIGNAL ;
    PORT
      LAYER M4 ;
        RECT  43.116 8.304 43.2 8.328 ;
    END
  END d[26]
  PIN d[270]
    DIRECTION INPUT ;
    USE SIGNAL ;
    PORT
      LAYER M4 ;
        RECT  43.116 55.536 43.2 55.56 ;
    END
  END d[270]
  PIN d[271]
    DIRECTION INPUT ;
    USE SIGNAL ;
    PORT
      LAYER M4 ;
        RECT  43.116 55.728 43.2 55.752 ;
    END
  END d[271]
  PIN d[272]
    DIRECTION INPUT ;
    USE SIGNAL ;
    PORT
      LAYER M4 ;
        RECT  43.116 55.92 43.2 55.944 ;
    END
  END d[272]
  PIN d[273]
    DIRECTION INPUT ;
    USE SIGNAL ;
    PORT
      LAYER M4 ;
        RECT  43.116 56.112 43.2 56.136 ;
    END
  END d[273]
  PIN d[274]
    DIRECTION INPUT ;
    USE SIGNAL ;
    PORT
      LAYER M4 ;
        RECT  43.116 56.304 43.2 56.328 ;
    END
  END d[274]
  PIN d[275]
    DIRECTION INPUT ;
    USE SIGNAL ;
    PORT
      LAYER M4 ;
        RECT  43.116 56.496 43.2 56.52 ;
    END
  END d[275]
  PIN d[276]
    DIRECTION INPUT ;
    USE SIGNAL ;
    PORT
      LAYER M4 ;
        RECT  43.116 56.688 43.2 56.712 ;
    END
  END d[276]
  PIN d[277]
    DIRECTION INPUT ;
    USE SIGNAL ;
    PORT
      LAYER M4 ;
        RECT  43.116 56.88 43.2 56.904 ;
    END
  END d[277]
  PIN d[278]
    DIRECTION INPUT ;
    USE SIGNAL ;
    PORT
      LAYER M4 ;
        RECT  43.116 57.072 43.2 57.096 ;
    END
  END d[278]
  PIN d[279]
    DIRECTION INPUT ;
    USE SIGNAL ;
    PORT
      LAYER M4 ;
        RECT  43.116 57.264 43.2 57.288 ;
    END
  END d[279]
  PIN d[27]
    DIRECTION INPUT ;
    USE SIGNAL ;
    PORT
      LAYER M4 ;
        RECT  43.116 8.496 43.2 8.52 ;
    END
  END d[27]
  PIN d[280]
    DIRECTION INPUT ;
    USE SIGNAL ;
    PORT
      LAYER M4 ;
        RECT  43.116 57.456 43.2 57.48 ;
    END
  END d[280]
  PIN d[281]
    DIRECTION INPUT ;
    USE SIGNAL ;
    PORT
      LAYER M4 ;
        RECT  43.116 57.84 43.2 57.864 ;
    END
  END d[281]
  PIN d[282]
    DIRECTION INPUT ;
    USE SIGNAL ;
    PORT
      LAYER M4 ;
        RECT  43.116 57.648 43.2 57.672 ;
    END
  END d[282]
  PIN d[283]
    DIRECTION INPUT ;
    USE SIGNAL ;
    PORT
      LAYER M4 ;
        RECT  43.116 58.032 43.2 58.056 ;
    END
  END d[283]
  PIN d[284]
    DIRECTION INPUT ;
    USE SIGNAL ;
    PORT
      LAYER M4 ;
        RECT  43.116 58.416 43.2 58.44 ;
    END
  END d[284]
  PIN d[285]
    DIRECTION INPUT ;
    USE SIGNAL ;
    PORT
      LAYER M4 ;
        RECT  43.116 58.224 43.2 58.248 ;
    END
  END d[285]
  PIN d[286]
    DIRECTION INPUT ;
    USE SIGNAL ;
    PORT
      LAYER M4 ;
        RECT  43.116 58.608 43.2 58.632 ;
    END
  END d[286]
  PIN d[287]
    DIRECTION INPUT ;
    USE SIGNAL ;
    PORT
      LAYER M4 ;
        RECT  43.116 58.8 43.2 58.824 ;
    END
  END d[287]
  PIN d[288]
    DIRECTION INPUT ;
    USE SIGNAL ;
    PORT
      LAYER M4 ;
        RECT  43.116 58.992 43.2 59.016 ;
    END
  END d[288]
  PIN d[289]
    DIRECTION INPUT ;
    USE SIGNAL ;
    PORT
      LAYER M4 ;
        RECT  43.116 59.184 43.2 59.208 ;
    END
  END d[289]
  PIN d[28]
    DIRECTION INPUT ;
    USE SIGNAL ;
    PORT
      LAYER M4 ;
        RECT  43.116 8.688 43.2 8.712 ;
    END
  END d[28]
  PIN d[290]
    DIRECTION INPUT ;
    USE SIGNAL ;
    PORT
      LAYER M4 ;
        RECT  43.116 59.376 43.2 59.4 ;
    END
  END d[290]
  PIN d[291]
    DIRECTION INPUT ;
    USE SIGNAL ;
    PORT
      LAYER M4 ;
        RECT  43.116 59.568 43.2 59.592 ;
    END
  END d[291]
  PIN d[292]
    DIRECTION INPUT ;
    USE SIGNAL ;
    PORT
      LAYER M4 ;
        RECT  43.116 59.76 43.2 59.784 ;
    END
  END d[292]
  PIN d[293]
    DIRECTION INPUT ;
    USE SIGNAL ;
    PORT
      LAYER M4 ;
        RECT  43.116 59.952 43.2 59.976 ;
    END
  END d[293]
  PIN d[294]
    DIRECTION INPUT ;
    USE SIGNAL ;
    PORT
      LAYER M4 ;
        RECT  43.116 60.144 43.2 60.168 ;
    END
  END d[294]
  PIN d[295]
    DIRECTION INPUT ;
    USE SIGNAL ;
    PORT
      LAYER M4 ;
        RECT  43.116 60.336 43.2 60.36 ;
    END
  END d[295]
  PIN d[296]
    DIRECTION INPUT ;
    USE SIGNAL ;
    PORT
      LAYER M4 ;
        RECT  43.116 60.528 43.2 60.552 ;
    END
  END d[296]
  PIN d[297]
    DIRECTION INPUT ;
    USE SIGNAL ;
    PORT
      LAYER M4 ;
        RECT  43.116 60.72 43.2 60.744 ;
    END
  END d[297]
  PIN d[298]
    DIRECTION INPUT ;
    USE SIGNAL ;
    PORT
      LAYER M4 ;
        RECT  43.116 60.912 43.2 60.936 ;
    END
  END d[298]
  PIN d[299]
    DIRECTION INPUT ;
    USE SIGNAL ;
    PORT
      LAYER M4 ;
        RECT  43.116 61.104 43.2 61.128 ;
    END
  END d[299]
  PIN d[29]
    DIRECTION INPUT ;
    USE SIGNAL ;
    PORT
      LAYER M4 ;
        RECT  43.116 8.88 43.2 8.904 ;
    END
  END d[29]
  PIN d[2]
    DIRECTION INPUT ;
    USE SIGNAL ;
    PORT
      LAYER M4 ;
        RECT  43.116 3.696 43.2 3.72 ;
    END
  END d[2]
  PIN d[300]
    DIRECTION INPUT ;
    USE SIGNAL ;
    PORT
      LAYER M4 ;
        RECT  43.116 61.296 43.2 61.32 ;
    END
  END d[300]
  PIN d[301]
    DIRECTION INPUT ;
    USE SIGNAL ;
    PORT
      LAYER M4 ;
        RECT  43.116 61.872 43.2 61.896 ;
    END
  END d[301]
  PIN d[302]
    DIRECTION INPUT ;
    USE SIGNAL ;
    PORT
      LAYER M4 ;
        RECT  43.116 61.488 43.2 61.512 ;
    END
  END d[302]
  PIN d[303]
    DIRECTION INPUT ;
    USE SIGNAL ;
    PORT
      LAYER M4 ;
        RECT  43.116 62.064 43.2 62.088 ;
    END
  END d[303]
  PIN d[304]
    DIRECTION INPUT ;
    USE SIGNAL ;
    PORT
      LAYER M4 ;
        RECT  43.116 61.68 43.2 61.704 ;
    END
  END d[304]
  PIN d[305]
    DIRECTION INPUT ;
    USE SIGNAL ;
    PORT
      LAYER M4 ;
        RECT  43.116 62.256 43.2 62.28 ;
    END
  END d[305]
  PIN d[306]
    DIRECTION INPUT ;
    USE SIGNAL ;
    PORT
      LAYER M4 ;
        RECT  43.116 62.448 43.2 62.472 ;
    END
  END d[306]
  PIN d[307]
    DIRECTION INPUT ;
    USE SIGNAL ;
    PORT
      LAYER M4 ;
        RECT  43.116 62.64 43.2 62.664 ;
    END
  END d[307]
  PIN d[308]
    DIRECTION INPUT ;
    USE SIGNAL ;
    PORT
      LAYER M4 ;
        RECT  43.116 62.832 43.2 62.856 ;
    END
  END d[308]
  PIN d[309]
    DIRECTION INPUT ;
    USE SIGNAL ;
    PORT
      LAYER M4 ;
        RECT  43.116 63.024 43.2 63.048 ;
    END
  END d[309]
  PIN d[30]
    DIRECTION INPUT ;
    USE SIGNAL ;
    PORT
      LAYER M4 ;
        RECT  43.116 9.072 43.2 9.096 ;
    END
  END d[30]
  PIN d[310]
    DIRECTION INPUT ;
    USE SIGNAL ;
    PORT
      LAYER M4 ;
        RECT  43.116 63.216 43.2 63.24 ;
    END
  END d[310]
  PIN d[311]
    DIRECTION INPUT ;
    USE SIGNAL ;
    PORT
      LAYER M4 ;
        RECT  43.116 63.408 43.2 63.432 ;
    END
  END d[311]
  PIN d[312]
    DIRECTION INPUT ;
    USE SIGNAL ;
    PORT
      LAYER M4 ;
        RECT  43.116 63.6 43.2 63.624 ;
    END
  END d[312]
  PIN d[313]
    DIRECTION INPUT ;
    USE SIGNAL ;
    PORT
      LAYER M4 ;
        RECT  43.116 63.792 43.2 63.816 ;
    END
  END d[313]
  PIN d[314]
    DIRECTION INPUT ;
    USE SIGNAL ;
    PORT
      LAYER M4 ;
        RECT  43.116 63.984 43.2 64.008 ;
    END
  END d[314]
  PIN d[315]
    DIRECTION INPUT ;
    USE SIGNAL ;
    PORT
      LAYER M4 ;
        RECT  43.116 64.176 43.2 64.2 ;
    END
  END d[315]
  PIN d[316]
    DIRECTION INPUT ;
    USE SIGNAL ;
    PORT
      LAYER M4 ;
        RECT  43.116 64.368 43.2 64.392 ;
    END
  END d[316]
  PIN d[317]
    DIRECTION INPUT ;
    USE SIGNAL ;
    PORT
      LAYER M4 ;
        RECT  43.116 64.56 43.2 64.584 ;
    END
  END d[317]
  PIN d[318]
    DIRECTION INPUT ;
    USE SIGNAL ;
    PORT
      LAYER M4 ;
        RECT  43.116 64.752 43.2 64.776 ;
    END
  END d[318]
  PIN d[319]
    DIRECTION INPUT ;
    USE SIGNAL ;
    PORT
      LAYER M4 ;
        RECT  43.116 64.944 43.2 64.968 ;
    END
  END d[319]
  PIN d[31]
    DIRECTION INPUT ;
    USE SIGNAL ;
    PORT
      LAYER M4 ;
        RECT  43.116 9.264 43.2 9.288 ;
    END
  END d[31]
  PIN d[320]
    DIRECTION INPUT ;
    USE SIGNAL ;
    PORT
      LAYER M4 ;
        RECT  43.116 65.136 43.2 65.16 ;
    END
  END d[320]
  PIN d[321]
    DIRECTION INPUT ;
    USE SIGNAL ;
    PORT
      LAYER M4 ;
        RECT  43.116 65.328 43.2 65.352 ;
    END
  END d[321]
  PIN d[322]
    DIRECTION INPUT ;
    USE SIGNAL ;
    PORT
      LAYER M4 ;
        RECT  43.116 65.52 43.2 65.544 ;
    END
  END d[322]
  PIN d[323]
    DIRECTION INPUT ;
    USE SIGNAL ;
    PORT
      LAYER M4 ;
        RECT  43.116 65.904 43.2 65.928 ;
    END
  END d[323]
  PIN d[324]
    DIRECTION INPUT ;
    USE SIGNAL ;
    PORT
      LAYER M4 ;
        RECT  43.116 65.712 43.2 65.736 ;
    END
  END d[324]
  PIN d[325]
    DIRECTION INPUT ;
    USE SIGNAL ;
    PORT
      LAYER M4 ;
        RECT  43.116 66.096 43.2 66.12 ;
    END
  END d[325]
  PIN d[326]
    DIRECTION INPUT ;
    USE SIGNAL ;
    PORT
      LAYER M4 ;
        RECT  43.116 66.288 43.2 66.312 ;
    END
  END d[326]
  PIN d[327]
    DIRECTION INPUT ;
    USE SIGNAL ;
    PORT
      LAYER M4 ;
        RECT  43.116 66.48 43.2 66.504 ;
    END
  END d[327]
  PIN d[328]
    DIRECTION INPUT ;
    USE SIGNAL ;
    PORT
      LAYER M4 ;
        RECT  43.116 66.672 43.2 66.696 ;
    END
  END d[328]
  PIN d[329]
    DIRECTION INPUT ;
    USE SIGNAL ;
    PORT
      LAYER M4 ;
        RECT  43.116 66.864 43.2 66.888 ;
    END
  END d[329]
  PIN d[32]
    DIRECTION INPUT ;
    USE SIGNAL ;
    PORT
      LAYER M4 ;
        RECT  43.116 9.456 43.2 9.48 ;
    END
  END d[32]
  PIN d[330]
    DIRECTION INPUT ;
    USE SIGNAL ;
    PORT
      LAYER M4 ;
        RECT  43.116 67.056 43.2 67.08 ;
    END
  END d[330]
  PIN d[331]
    DIRECTION INPUT ;
    USE SIGNAL ;
    PORT
      LAYER M4 ;
        RECT  43.116 67.248 43.2 67.272 ;
    END
  END d[331]
  PIN d[332]
    DIRECTION INPUT ;
    USE SIGNAL ;
    PORT
      LAYER M4 ;
        RECT  43.116 67.44 43.2 67.464 ;
    END
  END d[332]
  PIN d[333]
    DIRECTION INPUT ;
    USE SIGNAL ;
    PORT
      LAYER M4 ;
        RECT  43.116 67.632 43.2 67.656 ;
    END
  END d[333]
  PIN d[334]
    DIRECTION INPUT ;
    USE SIGNAL ;
    PORT
      LAYER M4 ;
        RECT  43.116 67.824 43.2 67.848 ;
    END
  END d[334]
  PIN d[335]
    DIRECTION INPUT ;
    USE SIGNAL ;
    PORT
      LAYER M4 ;
        RECT  43.116 68.016 43.2 68.04 ;
    END
  END d[335]
  PIN d[336]
    DIRECTION INPUT ;
    USE SIGNAL ;
    PORT
      LAYER M4 ;
        RECT  43.116 68.208 43.2 68.232 ;
    END
  END d[336]
  PIN d[337]
    DIRECTION INPUT ;
    USE SIGNAL ;
    PORT
      LAYER M4 ;
        RECT  43.116 68.4 43.2 68.424 ;
    END
  END d[337]
  PIN d[338]
    DIRECTION INPUT ;
    USE SIGNAL ;
    PORT
      LAYER M4 ;
        RECT  43.116 68.592 43.2 68.616 ;
    END
  END d[338]
  PIN d[339]
    DIRECTION INPUT ;
    USE SIGNAL ;
    PORT
      LAYER M4 ;
        RECT  43.116 68.784 43.2 68.808 ;
    END
  END d[339]
  PIN d[33]
    DIRECTION INPUT ;
    USE SIGNAL ;
    PORT
      LAYER M4 ;
        RECT  43.116 9.648 43.2 9.672 ;
    END
  END d[33]
  PIN d[340]
    DIRECTION INPUT ;
    USE SIGNAL ;
    PORT
      LAYER M4 ;
        RECT  43.116 68.976 43.2 69 ;
    END
  END d[340]
  PIN d[341]
    DIRECTION INPUT ;
    USE SIGNAL ;
    PORT
      LAYER M4 ;
        RECT  43.116 69.168 43.2 69.192 ;
    END
  END d[341]
  PIN d[342]
    DIRECTION INPUT ;
    USE SIGNAL ;
    PORT
      LAYER M4 ;
        RECT  43.116 69.36 43.2 69.384 ;
    END
  END d[342]
  PIN d[343]
    DIRECTION INPUT ;
    USE SIGNAL ;
    PORT
      LAYER M4 ;
        RECT  43.116 69.744 43.2 69.768 ;
    END
  END d[343]
  PIN d[344]
    DIRECTION INPUT ;
    USE SIGNAL ;
    PORT
      LAYER M4 ;
        RECT  43.116 69.552 43.2 69.576 ;
    END
  END d[344]
  PIN d[345]
    DIRECTION INPUT ;
    USE SIGNAL ;
    PORT
      LAYER M4 ;
        RECT  43.116 69.936 43.2 69.96 ;
    END
  END d[345]
  PIN d[346]
    DIRECTION INPUT ;
    USE SIGNAL ;
    PORT
      LAYER M4 ;
        RECT  43.116 70.128 43.2 70.152 ;
    END
  END d[346]
  PIN d[347]
    DIRECTION INPUT ;
    USE SIGNAL ;
    PORT
      LAYER M4 ;
        RECT  43.116 70.32 43.2 70.344 ;
    END
  END d[347]
  PIN d[348]
    DIRECTION INPUT ;
    USE SIGNAL ;
    PORT
      LAYER M4 ;
        RECT  43.116 70.512 43.2 70.536 ;
    END
  END d[348]
  PIN d[349]
    DIRECTION INPUT ;
    USE SIGNAL ;
    PORT
      LAYER M4 ;
        RECT  43.116 70.704 43.2 70.728 ;
    END
  END d[349]
  PIN d[34]
    DIRECTION INPUT ;
    USE SIGNAL ;
    PORT
      LAYER M4 ;
        RECT  43.116 10.032 43.2 10.056 ;
    END
  END d[34]
  PIN d[350]
    DIRECTION INPUT ;
    USE SIGNAL ;
    PORT
      LAYER M4 ;
        RECT  43.116 70.896 43.2 70.92 ;
    END
  END d[350]
  PIN d[351]
    DIRECTION INPUT ;
    USE SIGNAL ;
    PORT
      LAYER M4 ;
        RECT  43.116 71.088 43.2 71.112 ;
    END
  END d[351]
  PIN d[352]
    DIRECTION INPUT ;
    USE SIGNAL ;
    PORT
      LAYER M4 ;
        RECT  43.116 71.28 43.2 71.304 ;
    END
  END d[352]
  PIN d[353]
    DIRECTION INPUT ;
    USE SIGNAL ;
    PORT
      LAYER M4 ;
        RECT  43.116 71.472 43.2 71.496 ;
    END
  END d[353]
  PIN d[354]
    DIRECTION INPUT ;
    USE SIGNAL ;
    PORT
      LAYER M4 ;
        RECT  43.116 71.664 43.2 71.688 ;
    END
  END d[354]
  PIN d[355]
    DIRECTION INPUT ;
    USE SIGNAL ;
    PORT
      LAYER M4 ;
        RECT  43.116 71.856 43.2 71.88 ;
    END
  END d[355]
  PIN d[356]
    DIRECTION INPUT ;
    USE SIGNAL ;
    PORT
      LAYER M4 ;
        RECT  43.116 72.048 43.2 72.072 ;
    END
  END d[356]
  PIN d[357]
    DIRECTION INPUT ;
    USE SIGNAL ;
    PORT
      LAYER M4 ;
        RECT  43.116 72.24 43.2 72.264 ;
    END
  END d[357]
  PIN d[358]
    DIRECTION INPUT ;
    USE SIGNAL ;
    PORT
      LAYER M4 ;
        RECT  43.116 72.432 43.2 72.456 ;
    END
  END d[358]
  PIN d[359]
    DIRECTION INPUT ;
    USE SIGNAL ;
    PORT
      LAYER M4 ;
        RECT  43.116 72.624 43.2 72.648 ;
    END
  END d[359]
  PIN d[35]
    DIRECTION INPUT ;
    USE SIGNAL ;
    PORT
      LAYER M4 ;
        RECT  43.116 9.84 43.2 9.864 ;
    END
  END d[35]
  PIN d[360]
    DIRECTION INPUT ;
    USE SIGNAL ;
    PORT
      LAYER M4 ;
        RECT  43.116 72.816 43.2 72.84 ;
    END
  END d[360]
  PIN d[361]
    DIRECTION INPUT ;
    USE SIGNAL ;
    PORT
      LAYER M4 ;
        RECT  43.116 73.008 43.2 73.032 ;
    END
  END d[361]
  PIN d[362]
    DIRECTION INPUT ;
    USE SIGNAL ;
    PORT
      LAYER M4 ;
        RECT  43.116 73.2 43.2 73.224 ;
    END
  END d[362]
  PIN d[363]
    DIRECTION INPUT ;
    USE SIGNAL ;
    PORT
      LAYER M4 ;
        RECT  43.116 73.584 43.2 73.608 ;
    END
  END d[363]
  PIN d[364]
    DIRECTION INPUT ;
    USE SIGNAL ;
    PORT
      LAYER M4 ;
        RECT  43.116 73.392 43.2 73.416 ;
    END
  END d[364]
  PIN d[365]
    DIRECTION INPUT ;
    USE SIGNAL ;
    PORT
      LAYER M4 ;
        RECT  43.116 73.968 43.2 73.992 ;
    END
  END d[365]
  PIN d[366]
    DIRECTION INPUT ;
    USE SIGNAL ;
    PORT
      LAYER M4 ;
        RECT  43.116 73.776 43.2 73.8 ;
    END
  END d[366]
  PIN d[367]
    DIRECTION INPUT ;
    USE SIGNAL ;
    PORT
      LAYER M4 ;
        RECT  43.116 74.16 43.2 74.184 ;
    END
  END d[367]
  PIN d[368]
    DIRECTION INPUT ;
    USE SIGNAL ;
    PORT
      LAYER M4 ;
        RECT  43.116 74.352 43.2 74.376 ;
    END
  END d[368]
  PIN d[369]
    DIRECTION INPUT ;
    USE SIGNAL ;
    PORT
      LAYER M4 ;
        RECT  43.116 74.544 43.2 74.568 ;
    END
  END d[369]
  PIN d[36]
    DIRECTION INPUT ;
    USE SIGNAL ;
    PORT
      LAYER M4 ;
        RECT  43.116 10.416 43.2 10.44 ;
    END
  END d[36]
  PIN d[370]
    DIRECTION INPUT ;
    USE SIGNAL ;
    PORT
      LAYER M4 ;
        RECT  43.116 74.736 43.2 74.76 ;
    END
  END d[370]
  PIN d[371]
    DIRECTION INPUT ;
    USE SIGNAL ;
    PORT
      LAYER M4 ;
        RECT  43.116 74.928 43.2 74.952 ;
    END
  END d[371]
  PIN d[372]
    DIRECTION INPUT ;
    USE SIGNAL ;
    PORT
      LAYER M4 ;
        RECT  43.116 75.12 43.2 75.144 ;
    END
  END d[372]
  PIN d[373]
    DIRECTION INPUT ;
    USE SIGNAL ;
    PORT
      LAYER M4 ;
        RECT  43.116 75.312 43.2 75.336 ;
    END
  END d[373]
  PIN d[374]
    DIRECTION INPUT ;
    USE SIGNAL ;
    PORT
      LAYER M4 ;
        RECT  43.116 75.504 43.2 75.528 ;
    END
  END d[374]
  PIN d[375]
    DIRECTION INPUT ;
    USE SIGNAL ;
    PORT
      LAYER M4 ;
        RECT  43.116 75.696 43.2 75.72 ;
    END
  END d[375]
  PIN d[376]
    DIRECTION INPUT ;
    USE SIGNAL ;
    PORT
      LAYER M4 ;
        RECT  43.116 75.888 43.2 75.912 ;
    END
  END d[376]
  PIN d[377]
    DIRECTION INPUT ;
    USE SIGNAL ;
    PORT
      LAYER M4 ;
        RECT  43.116 76.08 43.2 76.104 ;
    END
  END d[377]
  PIN d[378]
    DIRECTION INPUT ;
    USE SIGNAL ;
    PORT
      LAYER M4 ;
        RECT  43.116 76.272 43.2 76.296 ;
    END
  END d[378]
  PIN d[379]
    DIRECTION INPUT ;
    USE SIGNAL ;
    PORT
      LAYER M4 ;
        RECT  43.116 76.464 43.2 76.488 ;
    END
  END d[379]
  PIN d[37]
    DIRECTION INPUT ;
    USE SIGNAL ;
    PORT
      LAYER M4 ;
        RECT  43.116 10.224 43.2 10.248 ;
    END
  END d[37]
  PIN d[380]
    DIRECTION INPUT ;
    USE SIGNAL ;
    PORT
      LAYER M4 ;
        RECT  43.116 76.656 43.2 76.68 ;
    END
  END d[380]
  PIN d[381]
    DIRECTION INPUT ;
    USE SIGNAL ;
    PORT
      LAYER M4 ;
        RECT  43.116 76.848 43.2 76.872 ;
    END
  END d[381]
  PIN d[382]
    DIRECTION INPUT ;
    USE SIGNAL ;
    PORT
      LAYER M4 ;
        RECT  43.116 77.04 43.2 77.064 ;
    END
  END d[382]
  PIN d[383]
    DIRECTION INPUT ;
    USE SIGNAL ;
    PORT
      LAYER M4 ;
        RECT  43.116 77.232 43.2 77.256 ;
    END
  END d[383]
  PIN d[384]
    DIRECTION INPUT ;
    USE SIGNAL ;
    PORT
      LAYER M4 ;
        RECT  43.116 77.424 43.2 77.448 ;
    END
  END d[384]
  PIN d[385]
    DIRECTION INPUT ;
    USE SIGNAL ;
    PORT
      LAYER M4 ;
        RECT  43.116 77.808 43.2 77.832 ;
    END
  END d[385]
  PIN d[386]
    DIRECTION INPUT ;
    USE SIGNAL ;
    PORT
      LAYER M4 ;
        RECT  43.116 77.616 43.2 77.64 ;
    END
  END d[386]
  PIN d[387]
    DIRECTION INPUT ;
    USE SIGNAL ;
    PORT
      LAYER M4 ;
        RECT  43.116 78 43.2 78.024 ;
    END
  END d[387]
  PIN d[388]
    DIRECTION INPUT ;
    USE SIGNAL ;
    PORT
      LAYER M4 ;
        RECT  43.116 78.192 43.2 78.216 ;
    END
  END d[388]
  PIN d[389]
    DIRECTION INPUT ;
    USE SIGNAL ;
    PORT
      LAYER M4 ;
        RECT  43.116 78.384 43.2 78.408 ;
    END
  END d[389]
  PIN d[38]
    DIRECTION INPUT ;
    USE SIGNAL ;
    PORT
      LAYER M4 ;
        RECT  43.116 10.608 43.2 10.632 ;
    END
  END d[38]
  PIN d[390]
    DIRECTION INPUT ;
    USE SIGNAL ;
    PORT
      LAYER M4 ;
        RECT  43.116 78.576 43.2 78.6 ;
    END
  END d[390]
  PIN d[391]
    DIRECTION INPUT ;
    USE SIGNAL ;
    PORT
      LAYER M4 ;
        RECT  43.116 78.768 43.2 78.792 ;
    END
  END d[391]
  PIN d[392]
    DIRECTION INPUT ;
    USE SIGNAL ;
    PORT
      LAYER M4 ;
        RECT  43.116 78.96 43.2 78.984 ;
    END
  END d[392]
  PIN d[393]
    DIRECTION INPUT ;
    USE SIGNAL ;
    PORT
      LAYER M4 ;
        RECT  43.116 79.152 43.2 79.176 ;
    END
  END d[393]
  PIN d[394]
    DIRECTION INPUT ;
    USE SIGNAL ;
    PORT
      LAYER M4 ;
        RECT  43.116 79.344 43.2 79.368 ;
    END
  END d[394]
  PIN d[395]
    DIRECTION INPUT ;
    USE SIGNAL ;
    PORT
      LAYER M4 ;
        RECT  43.116 79.536 43.2 79.56 ;
    END
  END d[395]
  PIN d[396]
    DIRECTION INPUT ;
    USE SIGNAL ;
    PORT
      LAYER M4 ;
        RECT  43.116 79.728 43.2 79.752 ;
    END
  END d[396]
  PIN d[397]
    DIRECTION INPUT ;
    USE SIGNAL ;
    PORT
      LAYER M4 ;
        RECT  43.116 79.92 43.2 79.944 ;
    END
  END d[397]
  PIN d[398]
    DIRECTION INPUT ;
    USE SIGNAL ;
    PORT
      LAYER M4 ;
        RECT  43.116 80.112 43.2 80.136 ;
    END
  END d[398]
  PIN d[399]
    DIRECTION INPUT ;
    USE SIGNAL ;
    PORT
      LAYER M4 ;
        RECT  43.116 80.304 43.2 80.328 ;
    END
  END d[399]
  PIN d[39]
    DIRECTION INPUT ;
    USE SIGNAL ;
    PORT
      LAYER M4 ;
        RECT  43.116 10.8 43.2 10.824 ;
    END
  END d[39]
  PIN d[3]
    DIRECTION INPUT ;
    USE SIGNAL ;
    PORT
      LAYER M4 ;
        RECT  43.116 3.888 43.2 3.912 ;
    END
  END d[3]
  PIN d[400]
    DIRECTION INPUT ;
    USE SIGNAL ;
    PORT
      LAYER M4 ;
        RECT  43.116 80.496 43.2 80.52 ;
    END
  END d[400]
  PIN d[401]
    DIRECTION INPUT ;
    USE SIGNAL ;
    PORT
      LAYER M4 ;
        RECT  43.116 80.688 43.2 80.712 ;
    END
  END d[401]
  PIN d[402]
    DIRECTION INPUT ;
    USE SIGNAL ;
    PORT
      LAYER M4 ;
        RECT  43.116 80.88 43.2 80.904 ;
    END
  END d[402]
  PIN d[403]
    DIRECTION INPUT ;
    USE SIGNAL ;
    PORT
      LAYER M4 ;
        RECT  43.116 81.072 43.2 81.096 ;
    END
  END d[403]
  PIN d[404]
    DIRECTION INPUT ;
    USE SIGNAL ;
    PORT
      LAYER M4 ;
        RECT  43.116 81.264 43.2 81.288 ;
    END
  END d[404]
  PIN d[405]
    DIRECTION INPUT ;
    USE SIGNAL ;
    PORT
      LAYER M4 ;
        RECT  43.116 81.84 43.2 81.864 ;
    END
  END d[405]
  PIN d[406]
    DIRECTION INPUT ;
    USE SIGNAL ;
    PORT
      LAYER M4 ;
        RECT  43.116 81.456 43.2 81.48 ;
    END
  END d[406]
  PIN d[407]
    DIRECTION INPUT ;
    USE SIGNAL ;
    PORT
      LAYER M4 ;
        RECT  43.116 82.032 43.2 82.056 ;
    END
  END d[407]
  PIN d[408]
    DIRECTION INPUT ;
    USE SIGNAL ;
    PORT
      LAYER M4 ;
        RECT  43.116 81.648 43.2 81.672 ;
    END
  END d[408]
  PIN d[409]
    DIRECTION INPUT ;
    USE SIGNAL ;
    PORT
      LAYER M4 ;
        RECT  43.116 82.224 43.2 82.248 ;
    END
  END d[409]
  PIN d[40]
    DIRECTION INPUT ;
    USE SIGNAL ;
    PORT
      LAYER M4 ;
        RECT  43.116 10.992 43.2 11.016 ;
    END
  END d[40]
  PIN d[410]
    DIRECTION INPUT ;
    USE SIGNAL ;
    PORT
      LAYER M4 ;
        RECT  43.116 82.416 43.2 82.44 ;
    END
  END d[410]
  PIN d[411]
    DIRECTION INPUT ;
    USE SIGNAL ;
    PORT
      LAYER M4 ;
        RECT  43.116 82.608 43.2 82.632 ;
    END
  END d[411]
  PIN d[412]
    DIRECTION INPUT ;
    USE SIGNAL ;
    PORT
      LAYER M4 ;
        RECT  43.116 82.8 43.2 82.824 ;
    END
  END d[412]
  PIN d[413]
    DIRECTION INPUT ;
    USE SIGNAL ;
    PORT
      LAYER M4 ;
        RECT  43.116 82.992 43.2 83.016 ;
    END
  END d[413]
  PIN d[414]
    DIRECTION INPUT ;
    USE SIGNAL ;
    PORT
      LAYER M4 ;
        RECT  43.116 83.184 43.2 83.208 ;
    END
  END d[414]
  PIN d[415]
    DIRECTION INPUT ;
    USE SIGNAL ;
    PORT
      LAYER M4 ;
        RECT  43.116 83.376 43.2 83.4 ;
    END
  END d[415]
  PIN d[416]
    DIRECTION INPUT ;
    USE SIGNAL ;
    PORT
      LAYER M4 ;
        RECT  43.116 83.568 43.2 83.592 ;
    END
  END d[416]
  PIN d[417]
    DIRECTION INPUT ;
    USE SIGNAL ;
    PORT
      LAYER M4 ;
        RECT  43.116 83.76 43.2 83.784 ;
    END
  END d[417]
  PIN d[418]
    DIRECTION INPUT ;
    USE SIGNAL ;
    PORT
      LAYER M4 ;
        RECT  43.116 83.952 43.2 83.976 ;
    END
  END d[418]
  PIN d[419]
    DIRECTION INPUT ;
    USE SIGNAL ;
    PORT
      LAYER M4 ;
        RECT  43.116 84.144 43.2 84.168 ;
    END
  END d[419]
  PIN d[41]
    DIRECTION INPUT ;
    USE SIGNAL ;
    PORT
      LAYER M4 ;
        RECT  43.116 11.184 43.2 11.208 ;
    END
  END d[41]
  PIN d[420]
    DIRECTION INPUT ;
    USE SIGNAL ;
    PORT
      LAYER M4 ;
        RECT  43.116 84.336 43.2 84.36 ;
    END
  END d[420]
  PIN d[421]
    DIRECTION INPUT ;
    USE SIGNAL ;
    PORT
      LAYER M4 ;
        RECT  43.116 84.528 43.2 84.552 ;
    END
  END d[421]
  PIN d[422]
    DIRECTION INPUT ;
    USE SIGNAL ;
    PORT
      LAYER M4 ;
        RECT  43.116 84.72 43.2 84.744 ;
    END
  END d[422]
  PIN d[423]
    DIRECTION INPUT ;
    USE SIGNAL ;
    PORT
      LAYER M4 ;
        RECT  43.116 84.912 43.2 84.936 ;
    END
  END d[423]
  PIN d[424]
    DIRECTION INPUT ;
    USE SIGNAL ;
    PORT
      LAYER M4 ;
        RECT  43.116 85.104 43.2 85.128 ;
    END
  END d[424]
  PIN d[425]
    DIRECTION INPUT ;
    USE SIGNAL ;
    PORT
      LAYER M4 ;
        RECT  43.116 85.68 43.2 85.704 ;
    END
  END d[425]
  PIN d[426]
    DIRECTION INPUT ;
    USE SIGNAL ;
    PORT
      LAYER M4 ;
        RECT  43.116 85.296 43.2 85.32 ;
    END
  END d[426]
  PIN d[427]
    DIRECTION INPUT ;
    USE SIGNAL ;
    PORT
      LAYER M4 ;
        RECT  43.116 85.872 43.2 85.896 ;
    END
  END d[427]
  PIN d[428]
    DIRECTION INPUT ;
    USE SIGNAL ;
    PORT
      LAYER M4 ;
        RECT  43.116 85.488 43.2 85.512 ;
    END
  END d[428]
  PIN d[429]
    DIRECTION INPUT ;
    USE SIGNAL ;
    PORT
      LAYER M4 ;
        RECT  43.116 86.064 43.2 86.088 ;
    END
  END d[429]
  PIN d[42]
    DIRECTION INPUT ;
    USE SIGNAL ;
    PORT
      LAYER M4 ;
        RECT  43.116 11.376 43.2 11.4 ;
    END
  END d[42]
  PIN d[430]
    DIRECTION INPUT ;
    USE SIGNAL ;
    PORT
      LAYER M4 ;
        RECT  43.116 86.256 43.2 86.28 ;
    END
  END d[430]
  PIN d[431]
    DIRECTION INPUT ;
    USE SIGNAL ;
    PORT
      LAYER M4 ;
        RECT  43.116 86.448 43.2 86.472 ;
    END
  END d[431]
  PIN d[432]
    DIRECTION INPUT ;
    USE SIGNAL ;
    PORT
      LAYER M4 ;
        RECT  43.116 86.64 43.2 86.664 ;
    END
  END d[432]
  PIN d[433]
    DIRECTION INPUT ;
    USE SIGNAL ;
    PORT
      LAYER M4 ;
        RECT  43.116 86.832 43.2 86.856 ;
    END
  END d[433]
  PIN d[434]
    DIRECTION INPUT ;
    USE SIGNAL ;
    PORT
      LAYER M4 ;
        RECT  43.116 87.024 43.2 87.048 ;
    END
  END d[434]
  PIN d[435]
    DIRECTION INPUT ;
    USE SIGNAL ;
    PORT
      LAYER M4 ;
        RECT  43.116 87.216 43.2 87.24 ;
    END
  END d[435]
  PIN d[436]
    DIRECTION INPUT ;
    USE SIGNAL ;
    PORT
      LAYER M4 ;
        RECT  43.116 87.408 43.2 87.432 ;
    END
  END d[436]
  PIN d[437]
    DIRECTION INPUT ;
    USE SIGNAL ;
    PORT
      LAYER M4 ;
        RECT  43.116 87.6 43.2 87.624 ;
    END
  END d[437]
  PIN d[438]
    DIRECTION INPUT ;
    USE SIGNAL ;
    PORT
      LAYER M4 ;
        RECT  43.116 87.792 43.2 87.816 ;
    END
  END d[438]
  PIN d[439]
    DIRECTION INPUT ;
    USE SIGNAL ;
    PORT
      LAYER M4 ;
        RECT  43.116 88.176 43.2 88.2 ;
    END
  END d[439]
  PIN d[43]
    DIRECTION INPUT ;
    USE SIGNAL ;
    PORT
      LAYER M4 ;
        RECT  43.116 11.568 43.2 11.592 ;
    END
  END d[43]
  PIN d[440]
    DIRECTION INPUT ;
    USE SIGNAL ;
    PORT
      LAYER M4 ;
        RECT  43.116 87.984 43.2 88.008 ;
    END
  END d[440]
  PIN d[441]
    DIRECTION INPUT ;
    USE SIGNAL ;
    PORT
      LAYER M4 ;
        RECT  43.116 88.368 43.2 88.392 ;
    END
  END d[441]
  PIN d[442]
    DIRECTION INPUT ;
    USE SIGNAL ;
    PORT
      LAYER M4 ;
        RECT  43.116 88.56 43.2 88.584 ;
    END
  END d[442]
  PIN d[443]
    DIRECTION INPUT ;
    USE SIGNAL ;
    PORT
      LAYER M4 ;
        RECT  43.116 88.752 43.2 88.776 ;
    END
  END d[443]
  PIN d[444]
    DIRECTION INPUT ;
    USE SIGNAL ;
    PORT
      LAYER M4 ;
        RECT  43.116 88.944 43.2 88.968 ;
    END
  END d[444]
  PIN d[445]
    DIRECTION INPUT ;
    USE SIGNAL ;
    PORT
      LAYER M4 ;
        RECT  43.116 89.136 43.2 89.16 ;
    END
  END d[445]
  PIN d[446]
    DIRECTION INPUT ;
    USE SIGNAL ;
    PORT
      LAYER M4 ;
        RECT  43.116 89.328 43.2 89.352 ;
    END
  END d[446]
  PIN d[447]
    DIRECTION INPUT ;
    USE SIGNAL ;
    PORT
      LAYER M4 ;
        RECT  43.116 89.712 43.2 89.736 ;
    END
  END d[447]
  PIN d[448]
    DIRECTION INPUT ;
    USE SIGNAL ;
    PORT
      LAYER M4 ;
        RECT  43.116 89.52 43.2 89.544 ;
    END
  END d[448]
  PIN d[449]
    DIRECTION INPUT ;
    USE SIGNAL ;
    PORT
      LAYER M4 ;
        RECT  43.116 89.904 43.2 89.928 ;
    END
  END d[449]
  PIN d[44]
    DIRECTION INPUT ;
    USE SIGNAL ;
    PORT
      LAYER M4 ;
        RECT  43.116 11.76 43.2 11.784 ;
    END
  END d[44]
  PIN d[450]
    DIRECTION INPUT ;
    USE SIGNAL ;
    PORT
      LAYER M4 ;
        RECT  43.116 90.096 43.2 90.12 ;
    END
  END d[450]
  PIN d[451]
    DIRECTION INPUT ;
    USE SIGNAL ;
    PORT
      LAYER M4 ;
        RECT  43.116 90.48 43.2 90.504 ;
    END
  END d[451]
  PIN d[452]
    DIRECTION INPUT ;
    USE SIGNAL ;
    PORT
      LAYER M4 ;
        RECT  43.116 90.288 43.2 90.312 ;
    END
  END d[452]
  PIN d[453]
    DIRECTION INPUT ;
    USE SIGNAL ;
    PORT
      LAYER M4 ;
        RECT  43.116 90.672 43.2 90.696 ;
    END
  END d[453]
  PIN d[454]
    DIRECTION INPUT ;
    USE SIGNAL ;
    PORT
      LAYER M4 ;
        RECT  43.116 90.864 43.2 90.888 ;
    END
  END d[454]
  PIN d[455]
    DIRECTION INPUT ;
    USE SIGNAL ;
    PORT
      LAYER M4 ;
        RECT  43.116 91.056 43.2 91.08 ;
    END
  END d[455]
  PIN d[456]
    DIRECTION INPUT ;
    USE SIGNAL ;
    PORT
      LAYER M4 ;
        RECT  43.116 91.248 43.2 91.272 ;
    END
  END d[456]
  PIN d[45]
    DIRECTION INPUT ;
    USE SIGNAL ;
    PORT
      LAYER M4 ;
        RECT  43.116 11.952 43.2 11.976 ;
    END
  END d[45]
  PIN d[46]
    DIRECTION INPUT ;
    USE SIGNAL ;
    PORT
      LAYER M4 ;
        RECT  43.116 12.144 43.2 12.168 ;
    END
  END d[46]
  PIN d[47]
    DIRECTION INPUT ;
    USE SIGNAL ;
    PORT
      LAYER M4 ;
        RECT  43.116 12.336 43.2 12.36 ;
    END
  END d[47]
  PIN d[48]
    DIRECTION INPUT ;
    USE SIGNAL ;
    PORT
      LAYER M4 ;
        RECT  43.116 12.528 43.2 12.552 ;
    END
  END d[48]
  PIN d[49]
    DIRECTION INPUT ;
    USE SIGNAL ;
    PORT
      LAYER M4 ;
        RECT  43.116 12.72 43.2 12.744 ;
    END
  END d[49]
  PIN d[4]
    DIRECTION INPUT ;
    USE SIGNAL ;
    PORT
      LAYER M4 ;
        RECT  43.116 4.08 43.2 4.104 ;
    END
  END d[4]
  PIN d[50]
    DIRECTION INPUT ;
    USE SIGNAL ;
    PORT
      LAYER M4 ;
        RECT  43.116 12.912 43.2 12.936 ;
    END
  END d[50]
  PIN d[51]
    DIRECTION INPUT ;
    USE SIGNAL ;
    PORT
      LAYER M4 ;
        RECT  43.116 13.104 43.2 13.128 ;
    END
  END d[51]
  PIN d[52]
    DIRECTION INPUT ;
    USE SIGNAL ;
    PORT
      LAYER M4 ;
        RECT  43.116 13.296 43.2 13.32 ;
    END
  END d[52]
  PIN d[53]
    DIRECTION INPUT ;
    USE SIGNAL ;
    PORT
      LAYER M4 ;
        RECT  43.116 13.488 43.2 13.512 ;
    END
  END d[53]
  PIN d[54]
    DIRECTION INPUT ;
    USE SIGNAL ;
    PORT
      LAYER M4 ;
        RECT  43.116 14.064 43.2 14.088 ;
    END
  END d[54]
  PIN d[55]
    DIRECTION INPUT ;
    USE SIGNAL ;
    PORT
      LAYER M4 ;
        RECT  43.116 13.68 43.2 13.704 ;
    END
  END d[55]
  PIN d[56]
    DIRECTION INPUT ;
    USE SIGNAL ;
    PORT
      LAYER M4 ;
        RECT  43.116 14.256 43.2 14.28 ;
    END
  END d[56]
  PIN d[57]
    DIRECTION INPUT ;
    USE SIGNAL ;
    PORT
      LAYER M4 ;
        RECT  43.116 13.872 43.2 13.896 ;
    END
  END d[57]
  PIN d[58]
    DIRECTION INPUT ;
    USE SIGNAL ;
    PORT
      LAYER M4 ;
        RECT  43.116 14.448 43.2 14.472 ;
    END
  END d[58]
  PIN d[59]
    DIRECTION INPUT ;
    USE SIGNAL ;
    PORT
      LAYER M4 ;
        RECT  43.116 14.64 43.2 14.664 ;
    END
  END d[59]
  PIN d[5]
    DIRECTION INPUT ;
    USE SIGNAL ;
    PORT
      LAYER M4 ;
        RECT  43.116 4.272 43.2 4.296 ;
    END
  END d[5]
  PIN d[60]
    DIRECTION INPUT ;
    USE SIGNAL ;
    PORT
      LAYER M4 ;
        RECT  43.116 14.832 43.2 14.856 ;
    END
  END d[60]
  PIN d[61]
    DIRECTION INPUT ;
    USE SIGNAL ;
    PORT
      LAYER M4 ;
        RECT  43.116 15.024 43.2 15.048 ;
    END
  END d[61]
  PIN d[62]
    DIRECTION INPUT ;
    USE SIGNAL ;
    PORT
      LAYER M4 ;
        RECT  43.116 15.216 43.2 15.24 ;
    END
  END d[62]
  PIN d[63]
    DIRECTION INPUT ;
    USE SIGNAL ;
    PORT
      LAYER M4 ;
        RECT  43.116 15.408 43.2 15.432 ;
    END
  END d[63]
  PIN d[64]
    DIRECTION INPUT ;
    USE SIGNAL ;
    PORT
      LAYER M4 ;
        RECT  43.116 15.6 43.2 15.624 ;
    END
  END d[64]
  PIN d[65]
    DIRECTION INPUT ;
    USE SIGNAL ;
    PORT
      LAYER M4 ;
        RECT  43.116 15.792 43.2 15.816 ;
    END
  END d[65]
  PIN d[66]
    DIRECTION INPUT ;
    USE SIGNAL ;
    PORT
      LAYER M4 ;
        RECT  43.116 15.984 43.2 16.008 ;
    END
  END d[66]
  PIN d[67]
    DIRECTION INPUT ;
    USE SIGNAL ;
    PORT
      LAYER M4 ;
        RECT  43.116 16.176 43.2 16.2 ;
    END
  END d[67]
  PIN d[68]
    DIRECTION INPUT ;
    USE SIGNAL ;
    PORT
      LAYER M4 ;
        RECT  43.116 16.368 43.2 16.392 ;
    END
  END d[68]
  PIN d[69]
    DIRECTION INPUT ;
    USE SIGNAL ;
    PORT
      LAYER M4 ;
        RECT  43.116 16.56 43.2 16.584 ;
    END
  END d[69]
  PIN d[6]
    DIRECTION INPUT ;
    USE SIGNAL ;
    PORT
      LAYER M4 ;
        RECT  43.116 4.464 43.2 4.488 ;
    END
  END d[6]
  PIN d[70]
    DIRECTION INPUT ;
    USE SIGNAL ;
    PORT
      LAYER M4 ;
        RECT  43.116 16.752 43.2 16.776 ;
    END
  END d[70]
  PIN d[71]
    DIRECTION INPUT ;
    USE SIGNAL ;
    PORT
      LAYER M4 ;
        RECT  43.116 16.944 43.2 16.968 ;
    END
  END d[71]
  PIN d[72]
    DIRECTION INPUT ;
    USE SIGNAL ;
    PORT
      LAYER M4 ;
        RECT  43.116 17.136 43.2 17.16 ;
    END
  END d[72]
  PIN d[73]
    DIRECTION INPUT ;
    USE SIGNAL ;
    PORT
      LAYER M4 ;
        RECT  43.116 17.328 43.2 17.352 ;
    END
  END d[73]
  PIN d[74]
    DIRECTION INPUT ;
    USE SIGNAL ;
    PORT
      LAYER M4 ;
        RECT  43.116 17.52 43.2 17.544 ;
    END
  END d[74]
  PIN d[75]
    DIRECTION INPUT ;
    USE SIGNAL ;
    PORT
      LAYER M4 ;
        RECT  43.116 17.712 43.2 17.736 ;
    END
  END d[75]
  PIN d[76]
    DIRECTION INPUT ;
    USE SIGNAL ;
    PORT
      LAYER M4 ;
        RECT  43.116 18.096 43.2 18.12 ;
    END
  END d[76]
  PIN d[77]
    DIRECTION INPUT ;
    USE SIGNAL ;
    PORT
      LAYER M4 ;
        RECT  43.116 17.904 43.2 17.928 ;
    END
  END d[77]
  PIN d[78]
    DIRECTION INPUT ;
    USE SIGNAL ;
    PORT
      LAYER M4 ;
        RECT  43.116 18.288 43.2 18.312 ;
    END
  END d[78]
  PIN d[79]
    DIRECTION INPUT ;
    USE SIGNAL ;
    PORT
      LAYER M4 ;
        RECT  43.116 18.48 43.2 18.504 ;
    END
  END d[79]
  PIN d[7]
    DIRECTION INPUT ;
    USE SIGNAL ;
    PORT
      LAYER M4 ;
        RECT  43.116 4.656 43.2 4.68 ;
    END
  END d[7]
  PIN d[80]
    DIRECTION INPUT ;
    USE SIGNAL ;
    PORT
      LAYER M4 ;
        RECT  43.116 18.672 43.2 18.696 ;
    END
  END d[80]
  PIN d[81]
    DIRECTION INPUT ;
    USE SIGNAL ;
    PORT
      LAYER M4 ;
        RECT  43.116 18.864 43.2 18.888 ;
    END
  END d[81]
  PIN d[82]
    DIRECTION INPUT ;
    USE SIGNAL ;
    PORT
      LAYER M4 ;
        RECT  43.116 19.056 43.2 19.08 ;
    END
  END d[82]
  PIN d[83]
    DIRECTION INPUT ;
    USE SIGNAL ;
    PORT
      LAYER M4 ;
        RECT  43.116 19.248 43.2 19.272 ;
    END
  END d[83]
  PIN d[84]
    DIRECTION INPUT ;
    USE SIGNAL ;
    PORT
      LAYER M4 ;
        RECT  43.116 19.44 43.2 19.464 ;
    END
  END d[84]
  PIN d[85]
    DIRECTION INPUT ;
    USE SIGNAL ;
    PORT
      LAYER M4 ;
        RECT  43.116 19.632 43.2 19.656 ;
    END
  END d[85]
  PIN d[86]
    DIRECTION INPUT ;
    USE SIGNAL ;
    PORT
      LAYER M4 ;
        RECT  43.116 19.824 43.2 19.848 ;
    END
  END d[86]
  PIN d[87]
    DIRECTION INPUT ;
    USE SIGNAL ;
    PORT
      LAYER M4 ;
        RECT  43.116 20.016 43.2 20.04 ;
    END
  END d[87]
  PIN d[88]
    DIRECTION INPUT ;
    USE SIGNAL ;
    PORT
      LAYER M4 ;
        RECT  43.116 20.208 43.2 20.232 ;
    END
  END d[88]
  PIN d[89]
    DIRECTION INPUT ;
    USE SIGNAL ;
    PORT
      LAYER M4 ;
        RECT  43.116 20.4 43.2 20.424 ;
    END
  END d[89]
  PIN d[8]
    DIRECTION INPUT ;
    USE SIGNAL ;
    PORT
      LAYER M4 ;
        RECT  43.116 5.04 43.2 5.064 ;
    END
  END d[8]
  PIN d[90]
    DIRECTION INPUT ;
    USE SIGNAL ;
    PORT
      LAYER M4 ;
        RECT  43.116 20.592 43.2 20.616 ;
    END
  END d[90]
  PIN d[91]
    DIRECTION INPUT ;
    USE SIGNAL ;
    PORT
      LAYER M4 ;
        RECT  43.116 20.784 43.2 20.808 ;
    END
  END d[91]
  PIN d[92]
    DIRECTION INPUT ;
    USE SIGNAL ;
    PORT
      LAYER M4 ;
        RECT  43.116 20.976 43.2 21 ;
    END
  END d[92]
  PIN d[93]
    DIRECTION INPUT ;
    USE SIGNAL ;
    PORT
      LAYER M4 ;
        RECT  43.116 21.168 43.2 21.192 ;
    END
  END d[93]
  PIN d[94]
    DIRECTION INPUT ;
    USE SIGNAL ;
    PORT
      LAYER M4 ;
        RECT  43.116 21.36 43.2 21.384 ;
    END
  END d[94]
  PIN d[95]
    DIRECTION INPUT ;
    USE SIGNAL ;
    PORT
      LAYER M4 ;
        RECT  43.116 21.552 43.2 21.576 ;
    END
  END d[95]
  PIN d[96]
    DIRECTION INPUT ;
    USE SIGNAL ;
    PORT
      LAYER M4 ;
        RECT  43.116 21.936 43.2 21.96 ;
    END
  END d[96]
  PIN d[97]
    DIRECTION INPUT ;
    USE SIGNAL ;
    PORT
      LAYER M4 ;
        RECT  43.116 21.744 43.2 21.768 ;
    END
  END d[97]
  PIN d[98]
    DIRECTION INPUT ;
    USE SIGNAL ;
    PORT
      LAYER M4 ;
        RECT  43.116 22.32 43.2 22.344 ;
    END
  END d[98]
  PIN d[99]
    DIRECTION INPUT ;
    USE SIGNAL ;
    PORT
      LAYER M4 ;
        RECT  43.116 22.128 43.2 22.152 ;
    END
  END d[99]
  PIN d[9]
    DIRECTION INPUT ;
    USE SIGNAL ;
    PORT
      LAYER M4 ;
        RECT  43.116 4.848 43.2 4.872 ;
    END
  END d[9]
  PIN fault
    DIRECTION OUTPUT ;
    USE SIGNAL ;
    PORT
      LAYER M4 ;
        RECT  0 46.896 0.084 46.92 ;
    END
  END fault
  PIN fclk
    DIRECTION INPUT ;
    USE SIGNAL ;
    PORT
      LAYER M4 ;
        RECT  43.116 47.088 43.2 47.112 ;
    END
  END fclk
  PIN q[0]
    DIRECTION OUTPUT ;
    USE SIGNAL ;
    PORT
      LAYER M4 ;
        RECT  0 2.544 0.084 2.568 ;
    END
  END q[0]
  PIN q[100]
    DIRECTION OUTPUT ;
    USE SIGNAL ;
    PORT
      LAYER M4 ;
        RECT  0 21.744 0.084 21.768 ;
    END
  END q[100]
  PIN q[101]
    DIRECTION OUTPUT ;
    USE SIGNAL ;
    PORT
      LAYER M4 ;
        RECT  0 21.936 0.084 21.96 ;
    END
  END q[101]
  PIN q[102]
    DIRECTION OUTPUT ;
    USE SIGNAL ;
    PORT
      LAYER M4 ;
        RECT  0 22.128 0.084 22.152 ;
    END
  END q[102]
  PIN q[103]
    DIRECTION OUTPUT ;
    USE SIGNAL ;
    PORT
      LAYER M4 ;
        RECT  0 22.32 0.084 22.344 ;
    END
  END q[103]
  PIN q[104]
    DIRECTION OUTPUT ;
    USE SIGNAL ;
    PORT
      LAYER M4 ;
        RECT  0 22.512 0.084 22.536 ;
    END
  END q[104]
  PIN q[105]
    DIRECTION OUTPUT ;
    USE SIGNAL ;
    PORT
      LAYER M4 ;
        RECT  0 22.704 0.084 22.728 ;
    END
  END q[105]
  PIN q[106]
    DIRECTION OUTPUT ;
    USE SIGNAL ;
    PORT
      LAYER M4 ;
        RECT  0 22.896 0.084 22.92 ;
    END
  END q[106]
  PIN q[107]
    DIRECTION OUTPUT ;
    USE SIGNAL ;
    PORT
      LAYER M4 ;
        RECT  0 23.088 0.084 23.112 ;
    END
  END q[107]
  PIN q[108]
    DIRECTION OUTPUT ;
    USE SIGNAL ;
    PORT
      LAYER M4 ;
        RECT  0 23.28 0.084 23.304 ;
    END
  END q[108]
  PIN q[109]
    DIRECTION OUTPUT ;
    USE SIGNAL ;
    PORT
      LAYER M4 ;
        RECT  0 23.472 0.084 23.496 ;
    END
  END q[109]
  PIN q[10]
    DIRECTION OUTPUT ;
    USE SIGNAL ;
    PORT
      LAYER M4 ;
        RECT  0 4.464 0.084 4.488 ;
    END
  END q[10]
  PIN q[110]
    DIRECTION OUTPUT ;
    USE SIGNAL ;
    PORT
      LAYER M4 ;
        RECT  0 23.664 0.084 23.688 ;
    END
  END q[110]
  PIN q[111]
    DIRECTION OUTPUT ;
    USE SIGNAL ;
    PORT
      LAYER M4 ;
        RECT  0 23.856 0.084 23.88 ;
    END
  END q[111]
  PIN q[112]
    DIRECTION OUTPUT ;
    USE SIGNAL ;
    PORT
      LAYER M4 ;
        RECT  0 24.048 0.084 24.072 ;
    END
  END q[112]
  PIN q[113]
    DIRECTION OUTPUT ;
    USE SIGNAL ;
    PORT
      LAYER M4 ;
        RECT  0 24.24 0.084 24.264 ;
    END
  END q[113]
  PIN q[114]
    DIRECTION OUTPUT ;
    USE SIGNAL ;
    PORT
      LAYER M4 ;
        RECT  0 24.432 0.084 24.456 ;
    END
  END q[114]
  PIN q[115]
    DIRECTION OUTPUT ;
    USE SIGNAL ;
    PORT
      LAYER M4 ;
        RECT  0 24.816 0.084 24.84 ;
    END
  END q[115]
  PIN q[116]
    DIRECTION OUTPUT ;
    USE SIGNAL ;
    PORT
      LAYER M4 ;
        RECT  0 24.624 0.084 24.648 ;
    END
  END q[116]
  PIN q[117]
    DIRECTION OUTPUT ;
    USE SIGNAL ;
    PORT
      LAYER M4 ;
        RECT  0 25.008 0.084 25.032 ;
    END
  END q[117]
  PIN q[118]
    DIRECTION OUTPUT ;
    USE SIGNAL ;
    PORT
      LAYER M4 ;
        RECT  0 25.392 0.084 25.416 ;
    END
  END q[118]
  PIN q[119]
    DIRECTION OUTPUT ;
    USE SIGNAL ;
    PORT
      LAYER M4 ;
        RECT  0 25.2 0.084 25.224 ;
    END
  END q[119]
  PIN q[11]
    DIRECTION OUTPUT ;
    USE SIGNAL ;
    PORT
      LAYER M4 ;
        RECT  0 4.656 0.084 4.68 ;
    END
  END q[11]
  PIN q[120]
    DIRECTION OUTPUT ;
    USE SIGNAL ;
    PORT
      LAYER M4 ;
        RECT  0 25.584 0.084 25.608 ;
    END
  END q[120]
  PIN q[121]
    DIRECTION OUTPUT ;
    USE SIGNAL ;
    PORT
      LAYER M4 ;
        RECT  0 25.776 0.084 25.8 ;
    END
  END q[121]
  PIN q[122]
    DIRECTION OUTPUT ;
    USE SIGNAL ;
    PORT
      LAYER M4 ;
        RECT  0 25.968 0.084 25.992 ;
    END
  END q[122]
  PIN q[123]
    DIRECTION OUTPUT ;
    USE SIGNAL ;
    PORT
      LAYER M4 ;
        RECT  0 26.16 0.084 26.184 ;
    END
  END q[123]
  PIN q[124]
    DIRECTION OUTPUT ;
    USE SIGNAL ;
    PORT
      LAYER M4 ;
        RECT  0 26.352 0.084 26.376 ;
    END
  END q[124]
  PIN q[125]
    DIRECTION OUTPUT ;
    USE SIGNAL ;
    PORT
      LAYER M4 ;
        RECT  0 26.544 0.084 26.568 ;
    END
  END q[125]
  PIN q[126]
    DIRECTION OUTPUT ;
    USE SIGNAL ;
    PORT
      LAYER M4 ;
        RECT  0 26.736 0.084 26.76 ;
    END
  END q[126]
  PIN q[127]
    DIRECTION OUTPUT ;
    USE SIGNAL ;
    PORT
      LAYER M4 ;
        RECT  0 26.928 0.084 26.952 ;
    END
  END q[127]
  PIN q[128]
    DIRECTION OUTPUT ;
    USE SIGNAL ;
    PORT
      LAYER M4 ;
        RECT  0 27.12 0.084 27.144 ;
    END
  END q[128]
  PIN q[129]
    DIRECTION OUTPUT ;
    USE SIGNAL ;
    PORT
      LAYER M4 ;
        RECT  0 27.312 0.084 27.336 ;
    END
  END q[129]
  PIN q[12]
    DIRECTION OUTPUT ;
    USE SIGNAL ;
    PORT
      LAYER M4 ;
        RECT  0 4.848 0.084 4.872 ;
    END
  END q[12]
  PIN q[130]
    DIRECTION OUTPUT ;
    USE SIGNAL ;
    PORT
      LAYER M4 ;
        RECT  0 27.504 0.084 27.528 ;
    END
  END q[130]
  PIN q[131]
    DIRECTION OUTPUT ;
    USE SIGNAL ;
    PORT
      LAYER M4 ;
        RECT  0 27.696 0.084 27.72 ;
    END
  END q[131]
  PIN q[132]
    DIRECTION OUTPUT ;
    USE SIGNAL ;
    PORT
      LAYER M4 ;
        RECT  0 27.888 0.084 27.912 ;
    END
  END q[132]
  PIN q[133]
    DIRECTION OUTPUT ;
    USE SIGNAL ;
    PORT
      LAYER M4 ;
        RECT  0 28.08 0.084 28.104 ;
    END
  END q[133]
  PIN q[134]
    DIRECTION OUTPUT ;
    USE SIGNAL ;
    PORT
      LAYER M4 ;
        RECT  0 28.272 0.084 28.296 ;
    END
  END q[134]
  PIN q[135]
    DIRECTION OUTPUT ;
    USE SIGNAL ;
    PORT
      LAYER M4 ;
        RECT  0 28.464 0.084 28.488 ;
    END
  END q[135]
  PIN q[136]
    DIRECTION OUTPUT ;
    USE SIGNAL ;
    PORT
      LAYER M4 ;
        RECT  0 28.656 0.084 28.68 ;
    END
  END q[136]
  PIN q[137]
    DIRECTION OUTPUT ;
    USE SIGNAL ;
    PORT
      LAYER M4 ;
        RECT  0 28.848 0.084 28.872 ;
    END
  END q[137]
  PIN q[138]
    DIRECTION OUTPUT ;
    USE SIGNAL ;
    PORT
      LAYER M4 ;
        RECT  0 29.232 0.084 29.256 ;
    END
  END q[138]
  PIN q[139]
    DIRECTION OUTPUT ;
    USE SIGNAL ;
    PORT
      LAYER M4 ;
        RECT  0 29.04 0.084 29.064 ;
    END
  END q[139]
  PIN q[13]
    DIRECTION OUTPUT ;
    USE SIGNAL ;
    PORT
      LAYER M4 ;
        RECT  0 5.04 0.084 5.064 ;
    END
  END q[13]
  PIN q[140]
    DIRECTION OUTPUT ;
    USE SIGNAL ;
    PORT
      LAYER M4 ;
        RECT  0 29.424 0.084 29.448 ;
    END
  END q[140]
  PIN q[141]
    DIRECTION OUTPUT ;
    USE SIGNAL ;
    PORT
      LAYER M4 ;
        RECT  0 29.616 0.084 29.64 ;
    END
  END q[141]
  PIN q[142]
    DIRECTION OUTPUT ;
    USE SIGNAL ;
    PORT
      LAYER M4 ;
        RECT  0 29.808 0.084 29.832 ;
    END
  END q[142]
  PIN q[143]
    DIRECTION OUTPUT ;
    USE SIGNAL ;
    PORT
      LAYER M4 ;
        RECT  0 30 0.084 30.024 ;
    END
  END q[143]
  PIN q[144]
    DIRECTION OUTPUT ;
    USE SIGNAL ;
    PORT
      LAYER M4 ;
        RECT  0 30.192 0.084 30.216 ;
    END
  END q[144]
  PIN q[145]
    DIRECTION OUTPUT ;
    USE SIGNAL ;
    PORT
      LAYER M4 ;
        RECT  0 30.384 0.084 30.408 ;
    END
  END q[145]
  PIN q[146]
    DIRECTION OUTPUT ;
    USE SIGNAL ;
    PORT
      LAYER M4 ;
        RECT  0 30.576 0.084 30.6 ;
    END
  END q[146]
  PIN q[147]
    DIRECTION OUTPUT ;
    USE SIGNAL ;
    PORT
      LAYER M4 ;
        RECT  0 30.768 0.084 30.792 ;
    END
  END q[147]
  PIN q[148]
    DIRECTION OUTPUT ;
    USE SIGNAL ;
    PORT
      LAYER M4 ;
        RECT  0 30.96 0.084 30.984 ;
    END
  END q[148]
  PIN q[149]
    DIRECTION OUTPUT ;
    USE SIGNAL ;
    PORT
      LAYER M4 ;
        RECT  0 31.152 0.084 31.176 ;
    END
  END q[149]
  PIN q[14]
    DIRECTION OUTPUT ;
    USE SIGNAL ;
    PORT
      LAYER M4 ;
        RECT  0 5.424 0.084 5.448 ;
    END
  END q[14]
  PIN q[150]
    DIRECTION OUTPUT ;
    USE SIGNAL ;
    PORT
      LAYER M4 ;
        RECT  0 31.344 0.084 31.368 ;
    END
  END q[150]
  PIN q[151]
    DIRECTION OUTPUT ;
    USE SIGNAL ;
    PORT
      LAYER M4 ;
        RECT  0 31.536 0.084 31.56 ;
    END
  END q[151]
  PIN q[152]
    DIRECTION OUTPUT ;
    USE SIGNAL ;
    PORT
      LAYER M4 ;
        RECT  0 31.728 0.084 31.752 ;
    END
  END q[152]
  PIN q[153]
    DIRECTION OUTPUT ;
    USE SIGNAL ;
    PORT
      LAYER M4 ;
        RECT  0 31.92 0.084 31.944 ;
    END
  END q[153]
  PIN q[154]
    DIRECTION OUTPUT ;
    USE SIGNAL ;
    PORT
      LAYER M4 ;
        RECT  0 32.112 0.084 32.136 ;
    END
  END q[154]
  PIN q[155]
    DIRECTION OUTPUT ;
    USE SIGNAL ;
    PORT
      LAYER M4 ;
        RECT  0 32.304 0.084 32.328 ;
    END
  END q[155]
  PIN q[156]
    DIRECTION OUTPUT ;
    USE SIGNAL ;
    PORT
      LAYER M4 ;
        RECT  0 32.496 0.084 32.52 ;
    END
  END q[156]
  PIN q[157]
    DIRECTION OUTPUT ;
    USE SIGNAL ;
    PORT
      LAYER M4 ;
        RECT  0 32.688 0.084 32.712 ;
    END
  END q[157]
  PIN q[158]
    DIRECTION OUTPUT ;
    USE SIGNAL ;
    PORT
      LAYER M4 ;
        RECT  0 33.072 0.084 33.096 ;
    END
  END q[158]
  PIN q[159]
    DIRECTION OUTPUT ;
    USE SIGNAL ;
    PORT
      LAYER M4 ;
        RECT  0 32.88 0.084 32.904 ;
    END
  END q[159]
  PIN q[15]
    DIRECTION OUTPUT ;
    USE SIGNAL ;
    PORT
      LAYER M4 ;
        RECT  0 5.232 0.084 5.256 ;
    END
  END q[15]
  PIN q[160]
    DIRECTION OUTPUT ;
    USE SIGNAL ;
    PORT
      LAYER M4 ;
        RECT  0 33.456 0.084 33.48 ;
    END
  END q[160]
  PIN q[161]
    DIRECTION OUTPUT ;
    USE SIGNAL ;
    PORT
      LAYER M4 ;
        RECT  0 33.264 0.084 33.288 ;
    END
  END q[161]
  PIN q[162]
    DIRECTION OUTPUT ;
    USE SIGNAL ;
    PORT
      LAYER M4 ;
        RECT  0 33.648 0.084 33.672 ;
    END
  END q[162]
  PIN q[163]
    DIRECTION OUTPUT ;
    USE SIGNAL ;
    PORT
      LAYER M4 ;
        RECT  0 33.84 0.084 33.864 ;
    END
  END q[163]
  PIN q[164]
    DIRECTION OUTPUT ;
    USE SIGNAL ;
    PORT
      LAYER M4 ;
        RECT  0 34.032 0.084 34.056 ;
    END
  END q[164]
  PIN q[165]
    DIRECTION OUTPUT ;
    USE SIGNAL ;
    PORT
      LAYER M4 ;
        RECT  0 34.224 0.084 34.248 ;
    END
  END q[165]
  PIN q[166]
    DIRECTION OUTPUT ;
    USE SIGNAL ;
    PORT
      LAYER M4 ;
        RECT  0 34.416 0.084 34.44 ;
    END
  END q[166]
  PIN q[167]
    DIRECTION OUTPUT ;
    USE SIGNAL ;
    PORT
      LAYER M4 ;
        RECT  0 34.608 0.084 34.632 ;
    END
  END q[167]
  PIN q[168]
    DIRECTION OUTPUT ;
    USE SIGNAL ;
    PORT
      LAYER M4 ;
        RECT  0 34.8 0.084 34.824 ;
    END
  END q[168]
  PIN q[169]
    DIRECTION OUTPUT ;
    USE SIGNAL ;
    PORT
      LAYER M4 ;
        RECT  0 34.992 0.084 35.016 ;
    END
  END q[169]
  PIN q[16]
    DIRECTION OUTPUT ;
    USE SIGNAL ;
    PORT
      LAYER M4 ;
        RECT  0 5.616 0.084 5.64 ;
    END
  END q[16]
  PIN q[170]
    DIRECTION OUTPUT ;
    USE SIGNAL ;
    PORT
      LAYER M4 ;
        RECT  0 35.184 0.084 35.208 ;
    END
  END q[170]
  PIN q[171]
    DIRECTION OUTPUT ;
    USE SIGNAL ;
    PORT
      LAYER M4 ;
        RECT  0 35.376 0.084 35.4 ;
    END
  END q[171]
  PIN q[172]
    DIRECTION OUTPUT ;
    USE SIGNAL ;
    PORT
      LAYER M4 ;
        RECT  0 35.568 0.084 35.592 ;
    END
  END q[172]
  PIN q[173]
    DIRECTION OUTPUT ;
    USE SIGNAL ;
    PORT
      LAYER M4 ;
        RECT  0 35.76 0.084 35.784 ;
    END
  END q[173]
  PIN q[174]
    DIRECTION OUTPUT ;
    USE SIGNAL ;
    PORT
      LAYER M4 ;
        RECT  0 35.952 0.084 35.976 ;
    END
  END q[174]
  PIN q[175]
    DIRECTION OUTPUT ;
    USE SIGNAL ;
    PORT
      LAYER M4 ;
        RECT  0 36.144 0.084 36.168 ;
    END
  END q[175]
  PIN q[176]
    DIRECTION OUTPUT ;
    USE SIGNAL ;
    PORT
      LAYER M4 ;
        RECT  0 36.336 0.084 36.36 ;
    END
  END q[176]
  PIN q[177]
    DIRECTION OUTPUT ;
    USE SIGNAL ;
    PORT
      LAYER M4 ;
        RECT  0 36.72 0.084 36.744 ;
    END
  END q[177]
  PIN q[178]
    DIRECTION OUTPUT ;
    USE SIGNAL ;
    PORT
      LAYER M4 ;
        RECT  0 36.528 0.084 36.552 ;
    END
  END q[178]
  PIN q[179]
    DIRECTION OUTPUT ;
    USE SIGNAL ;
    PORT
      LAYER M4 ;
        RECT  0 36.912 0.084 36.936 ;
    END
  END q[179]
  PIN q[17]
    DIRECTION OUTPUT ;
    USE SIGNAL ;
    PORT
      LAYER M4 ;
        RECT  0 5.808 0.084 5.832 ;
    END
  END q[17]
  PIN q[180]
    DIRECTION OUTPUT ;
    USE SIGNAL ;
    PORT
      LAYER M4 ;
        RECT  0 37.296 0.084 37.32 ;
    END
  END q[180]
  PIN q[181]
    DIRECTION OUTPUT ;
    USE SIGNAL ;
    PORT
      LAYER M4 ;
        RECT  0 37.104 0.084 37.128 ;
    END
  END q[181]
  PIN q[182]
    DIRECTION OUTPUT ;
    USE SIGNAL ;
    PORT
      LAYER M4 ;
        RECT  0 37.488 0.084 37.512 ;
    END
  END q[182]
  PIN q[183]
    DIRECTION OUTPUT ;
    USE SIGNAL ;
    PORT
      LAYER M4 ;
        RECT  0 37.68 0.084 37.704 ;
    END
  END q[183]
  PIN q[184]
    DIRECTION OUTPUT ;
    USE SIGNAL ;
    PORT
      LAYER M4 ;
        RECT  0 37.872 0.084 37.896 ;
    END
  END q[184]
  PIN q[185]
    DIRECTION OUTPUT ;
    USE SIGNAL ;
    PORT
      LAYER M4 ;
        RECT  0 38.064 0.084 38.088 ;
    END
  END q[185]
  PIN q[186]
    DIRECTION OUTPUT ;
    USE SIGNAL ;
    PORT
      LAYER M4 ;
        RECT  0 38.256 0.084 38.28 ;
    END
  END q[186]
  PIN q[187]
    DIRECTION OUTPUT ;
    USE SIGNAL ;
    PORT
      LAYER M4 ;
        RECT  0 38.448 0.084 38.472 ;
    END
  END q[187]
  PIN q[188]
    DIRECTION OUTPUT ;
    USE SIGNAL ;
    PORT
      LAYER M4 ;
        RECT  0 38.64 0.084 38.664 ;
    END
  END q[188]
  PIN q[189]
    DIRECTION OUTPUT ;
    USE SIGNAL ;
    PORT
      LAYER M4 ;
        RECT  0 38.832 0.084 38.856 ;
    END
  END q[189]
  PIN q[18]
    DIRECTION OUTPUT ;
    USE SIGNAL ;
    PORT
      LAYER M4 ;
        RECT  0 6 0.084 6.024 ;
    END
  END q[18]
  PIN q[190]
    DIRECTION OUTPUT ;
    USE SIGNAL ;
    PORT
      LAYER M4 ;
        RECT  0 39.024 0.084 39.048 ;
    END
  END q[190]
  PIN q[191]
    DIRECTION OUTPUT ;
    USE SIGNAL ;
    PORT
      LAYER M4 ;
        RECT  0 39.216 0.084 39.24 ;
    END
  END q[191]
  PIN q[192]
    DIRECTION OUTPUT ;
    USE SIGNAL ;
    PORT
      LAYER M4 ;
        RECT  0 39.408 0.084 39.432 ;
    END
  END q[192]
  PIN q[193]
    DIRECTION OUTPUT ;
    USE SIGNAL ;
    PORT
      LAYER M4 ;
        RECT  0 39.6 0.084 39.624 ;
    END
  END q[193]
  PIN q[194]
    DIRECTION OUTPUT ;
    USE SIGNAL ;
    PORT
      LAYER M4 ;
        RECT  0 39.792 0.084 39.816 ;
    END
  END q[194]
  PIN q[195]
    DIRECTION OUTPUT ;
    USE SIGNAL ;
    PORT
      LAYER M4 ;
        RECT  0 39.984 0.084 40.008 ;
    END
  END q[195]
  PIN q[196]
    DIRECTION OUTPUT ;
    USE SIGNAL ;
    PORT
      LAYER M4 ;
        RECT  0 40.176 0.084 40.2 ;
    END
  END q[196]
  PIN q[197]
    DIRECTION OUTPUT ;
    USE SIGNAL ;
    PORT
      LAYER M4 ;
        RECT  0 40.368 0.084 40.392 ;
    END
  END q[197]
  PIN q[198]
    DIRECTION OUTPUT ;
    USE SIGNAL ;
    PORT
      LAYER M4 ;
        RECT  0 40.56 0.084 40.584 ;
    END
  END q[198]
  PIN q[199]
    DIRECTION OUTPUT ;
    USE SIGNAL ;
    PORT
      LAYER M4 ;
        RECT  0 40.752 0.084 40.776 ;
    END
  END q[199]
  PIN q[19]
    DIRECTION OUTPUT ;
    USE SIGNAL ;
    PORT
      LAYER M4 ;
        RECT  0 6.192 0.084 6.216 ;
    END
  END q[19]
  PIN q[1]
    DIRECTION OUTPUT ;
    USE SIGNAL ;
    PORT
      LAYER M4 ;
        RECT  0 2.736 0.084 2.76 ;
    END
  END q[1]
  PIN q[200]
    DIRECTION OUTPUT ;
    USE SIGNAL ;
    PORT
      LAYER M4 ;
        RECT  0 41.136 0.084 41.16 ;
    END
  END q[200]
  PIN q[201]
    DIRECTION OUTPUT ;
    USE SIGNAL ;
    PORT
      LAYER M4 ;
        RECT  0 40.944 0.084 40.968 ;
    END
  END q[201]
  PIN q[202]
    DIRECTION OUTPUT ;
    USE SIGNAL ;
    PORT
      LAYER M4 ;
        RECT  0 41.328 0.084 41.352 ;
    END
  END q[202]
  PIN q[203]
    DIRECTION OUTPUT ;
    USE SIGNAL ;
    PORT
      LAYER M4 ;
        RECT  0 41.52 0.084 41.544 ;
    END
  END q[203]
  PIN q[204]
    DIRECTION OUTPUT ;
    USE SIGNAL ;
    PORT
      LAYER M4 ;
        RECT  0 41.712 0.084 41.736 ;
    END
  END q[204]
  PIN q[205]
    DIRECTION OUTPUT ;
    USE SIGNAL ;
    PORT
      LAYER M4 ;
        RECT  0 41.904 0.084 41.928 ;
    END
  END q[205]
  PIN q[206]
    DIRECTION OUTPUT ;
    USE SIGNAL ;
    PORT
      LAYER M4 ;
        RECT  0 42.096 0.084 42.12 ;
    END
  END q[206]
  PIN q[207]
    DIRECTION OUTPUT ;
    USE SIGNAL ;
    PORT
      LAYER M4 ;
        RECT  0 42.288 0.084 42.312 ;
    END
  END q[207]
  PIN q[208]
    DIRECTION OUTPUT ;
    USE SIGNAL ;
    PORT
      LAYER M4 ;
        RECT  0 42.48 0.084 42.504 ;
    END
  END q[208]
  PIN q[209]
    DIRECTION OUTPUT ;
    USE SIGNAL ;
    PORT
      LAYER M4 ;
        RECT  0 42.672 0.084 42.696 ;
    END
  END q[209]
  PIN q[20]
    DIRECTION OUTPUT ;
    USE SIGNAL ;
    PORT
      LAYER M4 ;
        RECT  0 6.384 0.084 6.408 ;
    END
  END q[20]
  PIN q[210]
    DIRECTION OUTPUT ;
    USE SIGNAL ;
    PORT
      LAYER M4 ;
        RECT  0 42.864 0.084 42.888 ;
    END
  END q[210]
  PIN q[211]
    DIRECTION OUTPUT ;
    USE SIGNAL ;
    PORT
      LAYER M4 ;
        RECT  0 43.056 0.084 43.08 ;
    END
  END q[211]
  PIN q[212]
    DIRECTION OUTPUT ;
    USE SIGNAL ;
    PORT
      LAYER M4 ;
        RECT  0 43.248 0.084 43.272 ;
    END
  END q[212]
  PIN q[213]
    DIRECTION OUTPUT ;
    USE SIGNAL ;
    PORT
      LAYER M4 ;
        RECT  0 43.44 0.084 43.464 ;
    END
  END q[213]
  PIN q[214]
    DIRECTION OUTPUT ;
    USE SIGNAL ;
    PORT
      LAYER M4 ;
        RECT  0 43.632 0.084 43.656 ;
    END
  END q[214]
  PIN q[215]
    DIRECTION OUTPUT ;
    USE SIGNAL ;
    PORT
      LAYER M4 ;
        RECT  0 43.824 0.084 43.848 ;
    END
  END q[215]
  PIN q[216]
    DIRECTION OUTPUT ;
    USE SIGNAL ;
    PORT
      LAYER M4 ;
        RECT  0 44.016 0.084 44.04 ;
    END
  END q[216]
  PIN q[217]
    DIRECTION OUTPUT ;
    USE SIGNAL ;
    PORT
      LAYER M4 ;
        RECT  0 44.208 0.084 44.232 ;
    END
  END q[217]
  PIN q[218]
    DIRECTION OUTPUT ;
    USE SIGNAL ;
    PORT
      LAYER M4 ;
        RECT  0 44.4 0.084 44.424 ;
    END
  END q[218]
  PIN q[219]
    DIRECTION OUTPUT ;
    USE SIGNAL ;
    PORT
      LAYER M4 ;
        RECT  0 44.592 0.084 44.616 ;
    END
  END q[219]
  PIN q[21]
    DIRECTION OUTPUT ;
    USE SIGNAL ;
    PORT
      LAYER M4 ;
        RECT  0 6.576 0.084 6.6 ;
    END
  END q[21]
  PIN q[220]
    DIRECTION OUTPUT ;
    USE SIGNAL ;
    PORT
      LAYER M4 ;
        RECT  0 44.976 0.084 45 ;
    END
  END q[220]
  PIN q[221]
    DIRECTION OUTPUT ;
    USE SIGNAL ;
    PORT
      LAYER M4 ;
        RECT  0 44.784 0.084 44.808 ;
    END
  END q[221]
  PIN q[222]
    DIRECTION OUTPUT ;
    USE SIGNAL ;
    PORT
      LAYER M4 ;
        RECT  0 45.36 0.084 45.384 ;
    END
  END q[222]
  PIN q[223]
    DIRECTION OUTPUT ;
    USE SIGNAL ;
    PORT
      LAYER M4 ;
        RECT  0 45.168 0.084 45.192 ;
    END
  END q[223]
  PIN q[224]
    DIRECTION OUTPUT ;
    USE SIGNAL ;
    PORT
      LAYER M4 ;
        RECT  0 45.552 0.084 45.576 ;
    END
  END q[224]
  PIN q[225]
    DIRECTION OUTPUT ;
    USE SIGNAL ;
    PORT
      LAYER M4 ;
        RECT  0 45.744 0.084 45.768 ;
    END
  END q[225]
  PIN q[226]
    DIRECTION OUTPUT ;
    USE SIGNAL ;
    PORT
      LAYER M4 ;
        RECT  0 45.936 0.084 45.96 ;
    END
  END q[226]
  PIN q[227]
    DIRECTION OUTPUT ;
    USE SIGNAL ;
    PORT
      LAYER M4 ;
        RECT  0 46.128 0.084 46.152 ;
    END
  END q[227]
  PIN q[228]
    DIRECTION OUTPUT ;
    USE SIGNAL ;
    PORT
      LAYER M4 ;
        RECT  0 48.24 0.084 48.264 ;
    END
  END q[228]
  PIN q[229]
    DIRECTION OUTPUT ;
    USE SIGNAL ;
    PORT
      LAYER M4 ;
        RECT  0 48.432 0.084 48.456 ;
    END
  END q[229]
  PIN q[22]
    DIRECTION OUTPUT ;
    USE SIGNAL ;
    PORT
      LAYER M4 ;
        RECT  0 6.768 0.084 6.792 ;
    END
  END q[22]
  PIN q[230]
    DIRECTION OUTPUT ;
    USE SIGNAL ;
    PORT
      LAYER M4 ;
        RECT  0 48.624 0.084 48.648 ;
    END
  END q[230]
  PIN q[231]
    DIRECTION OUTPUT ;
    USE SIGNAL ;
    PORT
      LAYER M4 ;
        RECT  0 48.816 0.084 48.84 ;
    END
  END q[231]
  PIN q[232]
    DIRECTION OUTPUT ;
    USE SIGNAL ;
    PORT
      LAYER M4 ;
        RECT  0 49.008 0.084 49.032 ;
    END
  END q[232]
  PIN q[233]
    DIRECTION OUTPUT ;
    USE SIGNAL ;
    PORT
      LAYER M4 ;
        RECT  0 49.2 0.084 49.224 ;
    END
  END q[233]
  PIN q[234]
    DIRECTION OUTPUT ;
    USE SIGNAL ;
    PORT
      LAYER M4 ;
        RECT  0 49.392 0.084 49.416 ;
    END
  END q[234]
  PIN q[235]
    DIRECTION OUTPUT ;
    USE SIGNAL ;
    PORT
      LAYER M4 ;
        RECT  0 49.584 0.084 49.608 ;
    END
  END q[235]
  PIN q[236]
    DIRECTION OUTPUT ;
    USE SIGNAL ;
    PORT
      LAYER M4 ;
        RECT  0 49.776 0.084 49.8 ;
    END
  END q[236]
  PIN q[237]
    DIRECTION OUTPUT ;
    USE SIGNAL ;
    PORT
      LAYER M4 ;
        RECT  0 49.968 0.084 49.992 ;
    END
  END q[237]
  PIN q[238]
    DIRECTION OUTPUT ;
    USE SIGNAL ;
    PORT
      LAYER M4 ;
        RECT  0 50.16 0.084 50.184 ;
    END
  END q[238]
  PIN q[239]
    DIRECTION OUTPUT ;
    USE SIGNAL ;
    PORT
      LAYER M4 ;
        RECT  0 50.544 0.084 50.568 ;
    END
  END q[239]
  PIN q[23]
    DIRECTION OUTPUT ;
    USE SIGNAL ;
    PORT
      LAYER M4 ;
        RECT  0 6.96 0.084 6.984 ;
    END
  END q[23]
  PIN q[240]
    DIRECTION OUTPUT ;
    USE SIGNAL ;
    PORT
      LAYER M4 ;
        RECT  0 50.352 0.084 50.376 ;
    END
  END q[240]
  PIN q[241]
    DIRECTION OUTPUT ;
    USE SIGNAL ;
    PORT
      LAYER M4 ;
        RECT  0 50.736 0.084 50.76 ;
    END
  END q[241]
  PIN q[242]
    DIRECTION OUTPUT ;
    USE SIGNAL ;
    PORT
      LAYER M4 ;
        RECT  0 51.12 0.084 51.144 ;
    END
  END q[242]
  PIN q[243]
    DIRECTION OUTPUT ;
    USE SIGNAL ;
    PORT
      LAYER M4 ;
        RECT  0 50.928 0.084 50.952 ;
    END
  END q[243]
  PIN q[244]
    DIRECTION OUTPUT ;
    USE SIGNAL ;
    PORT
      LAYER M4 ;
        RECT  0 51.312 0.084 51.336 ;
    END
  END q[244]
  PIN q[245]
    DIRECTION OUTPUT ;
    USE SIGNAL ;
    PORT
      LAYER M4 ;
        RECT  0 51.504 0.084 51.528 ;
    END
  END q[245]
  PIN q[246]
    DIRECTION OUTPUT ;
    USE SIGNAL ;
    PORT
      LAYER M4 ;
        RECT  0 51.696 0.084 51.72 ;
    END
  END q[246]
  PIN q[247]
    DIRECTION OUTPUT ;
    USE SIGNAL ;
    PORT
      LAYER M4 ;
        RECT  0 51.888 0.084 51.912 ;
    END
  END q[247]
  PIN q[248]
    DIRECTION OUTPUT ;
    USE SIGNAL ;
    PORT
      LAYER M4 ;
        RECT  0 52.08 0.084 52.104 ;
    END
  END q[248]
  PIN q[249]
    DIRECTION OUTPUT ;
    USE SIGNAL ;
    PORT
      LAYER M4 ;
        RECT  0 52.272 0.084 52.296 ;
    END
  END q[249]
  PIN q[24]
    DIRECTION OUTPUT ;
    USE SIGNAL ;
    PORT
      LAYER M4 ;
        RECT  0 7.152 0.084 7.176 ;
    END
  END q[24]
  PIN q[250]
    DIRECTION OUTPUT ;
    USE SIGNAL ;
    PORT
      LAYER M4 ;
        RECT  0 52.464 0.084 52.488 ;
    END
  END q[250]
  PIN q[251]
    DIRECTION OUTPUT ;
    USE SIGNAL ;
    PORT
      LAYER M4 ;
        RECT  0 52.656 0.084 52.68 ;
    END
  END q[251]
  PIN q[252]
    DIRECTION OUTPUT ;
    USE SIGNAL ;
    PORT
      LAYER M4 ;
        RECT  0 52.848 0.084 52.872 ;
    END
  END q[252]
  PIN q[253]
    DIRECTION OUTPUT ;
    USE SIGNAL ;
    PORT
      LAYER M4 ;
        RECT  0 53.04 0.084 53.064 ;
    END
  END q[253]
  PIN q[254]
    DIRECTION OUTPUT ;
    USE SIGNAL ;
    PORT
      LAYER M4 ;
        RECT  0 53.232 0.084 53.256 ;
    END
  END q[254]
  PIN q[255]
    DIRECTION OUTPUT ;
    USE SIGNAL ;
    PORT
      LAYER M4 ;
        RECT  0 53.424 0.084 53.448 ;
    END
  END q[255]
  PIN q[256]
    DIRECTION OUTPUT ;
    USE SIGNAL ;
    PORT
      LAYER M4 ;
        RECT  0 53.616 0.084 53.64 ;
    END
  END q[256]
  PIN q[257]
    DIRECTION OUTPUT ;
    USE SIGNAL ;
    PORT
      LAYER M4 ;
        RECT  0 53.808 0.084 53.832 ;
    END
  END q[257]
  PIN q[258]
    DIRECTION OUTPUT ;
    USE SIGNAL ;
    PORT
      LAYER M4 ;
        RECT  0 54 0.084 54.024 ;
    END
  END q[258]
  PIN q[259]
    DIRECTION OUTPUT ;
    USE SIGNAL ;
    PORT
      LAYER M4 ;
        RECT  0 54.192 0.084 54.216 ;
    END
  END q[259]
  PIN q[25]
    DIRECTION OUTPUT ;
    USE SIGNAL ;
    PORT
      LAYER M4 ;
        RECT  0 7.344 0.084 7.368 ;
    END
  END q[25]
  PIN q[260]
    DIRECTION OUTPUT ;
    USE SIGNAL ;
    PORT
      LAYER M4 ;
        RECT  0 54.384 0.084 54.408 ;
    END
  END q[260]
  PIN q[261]
    DIRECTION OUTPUT ;
    USE SIGNAL ;
    PORT
      LAYER M4 ;
        RECT  0 54.768 0.084 54.792 ;
    END
  END q[261]
  PIN q[262]
    DIRECTION OUTPUT ;
    USE SIGNAL ;
    PORT
      LAYER M4 ;
        RECT  0 54.576 0.084 54.6 ;
    END
  END q[262]
  PIN q[263]
    DIRECTION OUTPUT ;
    USE SIGNAL ;
    PORT
      LAYER M4 ;
        RECT  0 54.96 0.084 54.984 ;
    END
  END q[263]
  PIN q[264]
    DIRECTION OUTPUT ;
    USE SIGNAL ;
    PORT
      LAYER M4 ;
        RECT  0 55.152 0.084 55.176 ;
    END
  END q[264]
  PIN q[265]
    DIRECTION OUTPUT ;
    USE SIGNAL ;
    PORT
      LAYER M4 ;
        RECT  0 55.344 0.084 55.368 ;
    END
  END q[265]
  PIN q[266]
    DIRECTION OUTPUT ;
    USE SIGNAL ;
    PORT
      LAYER M4 ;
        RECT  0 55.536 0.084 55.56 ;
    END
  END q[266]
  PIN q[267]
    DIRECTION OUTPUT ;
    USE SIGNAL ;
    PORT
      LAYER M4 ;
        RECT  0 55.728 0.084 55.752 ;
    END
  END q[267]
  PIN q[268]
    DIRECTION OUTPUT ;
    USE SIGNAL ;
    PORT
      LAYER M4 ;
        RECT  0 55.92 0.084 55.944 ;
    END
  END q[268]
  PIN q[269]
    DIRECTION OUTPUT ;
    USE SIGNAL ;
    PORT
      LAYER M4 ;
        RECT  0 56.112 0.084 56.136 ;
    END
  END q[269]
  PIN q[26]
    DIRECTION OUTPUT ;
    USE SIGNAL ;
    PORT
      LAYER M4 ;
        RECT  0 7.536 0.084 7.56 ;
    END
  END q[26]
  PIN q[270]
    DIRECTION OUTPUT ;
    USE SIGNAL ;
    PORT
      LAYER M4 ;
        RECT  0 56.304 0.084 56.328 ;
    END
  END q[270]
  PIN q[271]
    DIRECTION OUTPUT ;
    USE SIGNAL ;
    PORT
      LAYER M4 ;
        RECT  0 56.496 0.084 56.52 ;
    END
  END q[271]
  PIN q[272]
    DIRECTION OUTPUT ;
    USE SIGNAL ;
    PORT
      LAYER M4 ;
        RECT  0 56.688 0.084 56.712 ;
    END
  END q[272]
  PIN q[273]
    DIRECTION OUTPUT ;
    USE SIGNAL ;
    PORT
      LAYER M4 ;
        RECT  0 56.88 0.084 56.904 ;
    END
  END q[273]
  PIN q[274]
    DIRECTION OUTPUT ;
    USE SIGNAL ;
    PORT
      LAYER M4 ;
        RECT  0 57.072 0.084 57.096 ;
    END
  END q[274]
  PIN q[275]
    DIRECTION OUTPUT ;
    USE SIGNAL ;
    PORT
      LAYER M4 ;
        RECT  0 57.264 0.084 57.288 ;
    END
  END q[275]
  PIN q[276]
    DIRECTION OUTPUT ;
    USE SIGNAL ;
    PORT
      LAYER M4 ;
        RECT  0 57.456 0.084 57.48 ;
    END
  END q[276]
  PIN q[277]
    DIRECTION OUTPUT ;
    USE SIGNAL ;
    PORT
      LAYER M4 ;
        RECT  0 57.648 0.084 57.672 ;
    END
  END q[277]
  PIN q[278]
    DIRECTION OUTPUT ;
    USE SIGNAL ;
    PORT
      LAYER M4 ;
        RECT  0 57.84 0.084 57.864 ;
    END
  END q[278]
  PIN q[279]
    DIRECTION OUTPUT ;
    USE SIGNAL ;
    PORT
      LAYER M4 ;
        RECT  0 58.032 0.084 58.056 ;
    END
  END q[279]
  PIN q[27]
    DIRECTION OUTPUT ;
    USE SIGNAL ;
    PORT
      LAYER M4 ;
        RECT  0 7.728 0.084 7.752 ;
    END
  END q[27]
  PIN q[280]
    DIRECTION OUTPUT ;
    USE SIGNAL ;
    PORT
      LAYER M4 ;
        RECT  0 58.224 0.084 58.248 ;
    END
  END q[280]
  PIN q[281]
    DIRECTION OUTPUT ;
    USE SIGNAL ;
    PORT
      LAYER M4 ;
        RECT  0 58.608 0.084 58.632 ;
    END
  END q[281]
  PIN q[282]
    DIRECTION OUTPUT ;
    USE SIGNAL ;
    PORT
      LAYER M4 ;
        RECT  0 58.416 0.084 58.44 ;
    END
  END q[282]
  PIN q[283]
    DIRECTION OUTPUT ;
    USE SIGNAL ;
    PORT
      LAYER M4 ;
        RECT  0 58.8 0.084 58.824 ;
    END
  END q[283]
  PIN q[284]
    DIRECTION OUTPUT ;
    USE SIGNAL ;
    PORT
      LAYER M4 ;
        RECT  0 59.184 0.084 59.208 ;
    END
  END q[284]
  PIN q[285]
    DIRECTION OUTPUT ;
    USE SIGNAL ;
    PORT
      LAYER M4 ;
        RECT  0 58.992 0.084 59.016 ;
    END
  END q[285]
  PIN q[286]
    DIRECTION OUTPUT ;
    USE SIGNAL ;
    PORT
      LAYER M4 ;
        RECT  0 59.376 0.084 59.4 ;
    END
  END q[286]
  PIN q[287]
    DIRECTION OUTPUT ;
    USE SIGNAL ;
    PORT
      LAYER M4 ;
        RECT  0 59.568 0.084 59.592 ;
    END
  END q[287]
  PIN q[288]
    DIRECTION OUTPUT ;
    USE SIGNAL ;
    PORT
      LAYER M4 ;
        RECT  0 59.76 0.084 59.784 ;
    END
  END q[288]
  PIN q[289]
    DIRECTION OUTPUT ;
    USE SIGNAL ;
    PORT
      LAYER M4 ;
        RECT  0 59.952 0.084 59.976 ;
    END
  END q[289]
  PIN q[28]
    DIRECTION OUTPUT ;
    USE SIGNAL ;
    PORT
      LAYER M4 ;
        RECT  0 7.92 0.084 7.944 ;
    END
  END q[28]
  PIN q[290]
    DIRECTION OUTPUT ;
    USE SIGNAL ;
    PORT
      LAYER M4 ;
        RECT  0 60.144 0.084 60.168 ;
    END
  END q[290]
  PIN q[291]
    DIRECTION OUTPUT ;
    USE SIGNAL ;
    PORT
      LAYER M4 ;
        RECT  0 60.336 0.084 60.36 ;
    END
  END q[291]
  PIN q[292]
    DIRECTION OUTPUT ;
    USE SIGNAL ;
    PORT
      LAYER M4 ;
        RECT  0 60.528 0.084 60.552 ;
    END
  END q[292]
  PIN q[293]
    DIRECTION OUTPUT ;
    USE SIGNAL ;
    PORT
      LAYER M4 ;
        RECT  0 60.72 0.084 60.744 ;
    END
  END q[293]
  PIN q[294]
    DIRECTION OUTPUT ;
    USE SIGNAL ;
    PORT
      LAYER M4 ;
        RECT  0 60.912 0.084 60.936 ;
    END
  END q[294]
  PIN q[295]
    DIRECTION OUTPUT ;
    USE SIGNAL ;
    PORT
      LAYER M4 ;
        RECT  0 61.104 0.084 61.128 ;
    END
  END q[295]
  PIN q[296]
    DIRECTION OUTPUT ;
    USE SIGNAL ;
    PORT
      LAYER M4 ;
        RECT  0 61.296 0.084 61.32 ;
    END
  END q[296]
  PIN q[297]
    DIRECTION OUTPUT ;
    USE SIGNAL ;
    PORT
      LAYER M4 ;
        RECT  0 61.488 0.084 61.512 ;
    END
  END q[297]
  PIN q[298]
    DIRECTION OUTPUT ;
    USE SIGNAL ;
    PORT
      LAYER M4 ;
        RECT  0 61.68 0.084 61.704 ;
    END
  END q[298]
  PIN q[299]
    DIRECTION OUTPUT ;
    USE SIGNAL ;
    PORT
      LAYER M4 ;
        RECT  0 61.872 0.084 61.896 ;
    END
  END q[299]
  PIN q[29]
    DIRECTION OUTPUT ;
    USE SIGNAL ;
    PORT
      LAYER M4 ;
        RECT  0 8.112 0.084 8.136 ;
    END
  END q[29]
  PIN q[2]
    DIRECTION OUTPUT ;
    USE SIGNAL ;
    PORT
      LAYER M4 ;
        RECT  0 2.928 0.084 2.952 ;
    END
  END q[2]
  PIN q[300]
    DIRECTION OUTPUT ;
    USE SIGNAL ;
    PORT
      LAYER M4 ;
        RECT  0 62.064 0.084 62.088 ;
    END
  END q[300]
  PIN q[301]
    DIRECTION OUTPUT ;
    USE SIGNAL ;
    PORT
      LAYER M4 ;
        RECT  0 62.64 0.084 62.664 ;
    END
  END q[301]
  PIN q[302]
    DIRECTION OUTPUT ;
    USE SIGNAL ;
    PORT
      LAYER M4 ;
        RECT  0 62.256 0.084 62.28 ;
    END
  END q[302]
  PIN q[303]
    DIRECTION OUTPUT ;
    USE SIGNAL ;
    PORT
      LAYER M4 ;
        RECT  0 62.832 0.084 62.856 ;
    END
  END q[303]
  PIN q[304]
    DIRECTION OUTPUT ;
    USE SIGNAL ;
    PORT
      LAYER M4 ;
        RECT  0 62.448 0.084 62.472 ;
    END
  END q[304]
  PIN q[305]
    DIRECTION OUTPUT ;
    USE SIGNAL ;
    PORT
      LAYER M4 ;
        RECT  0 63.024 0.084 63.048 ;
    END
  END q[305]
  PIN q[306]
    DIRECTION OUTPUT ;
    USE SIGNAL ;
    PORT
      LAYER M4 ;
        RECT  0 63.216 0.084 63.24 ;
    END
  END q[306]
  PIN q[307]
    DIRECTION OUTPUT ;
    USE SIGNAL ;
    PORT
      LAYER M4 ;
        RECT  0 63.408 0.084 63.432 ;
    END
  END q[307]
  PIN q[308]
    DIRECTION OUTPUT ;
    USE SIGNAL ;
    PORT
      LAYER M4 ;
        RECT  0 63.6 0.084 63.624 ;
    END
  END q[308]
  PIN q[309]
    DIRECTION OUTPUT ;
    USE SIGNAL ;
    PORT
      LAYER M4 ;
        RECT  0 63.792 0.084 63.816 ;
    END
  END q[309]
  PIN q[30]
    DIRECTION OUTPUT ;
    USE SIGNAL ;
    PORT
      LAYER M4 ;
        RECT  0 8.304 0.084 8.328 ;
    END
  END q[30]
  PIN q[310]
    DIRECTION OUTPUT ;
    USE SIGNAL ;
    PORT
      LAYER M4 ;
        RECT  0 63.984 0.084 64.008 ;
    END
  END q[310]
  PIN q[311]
    DIRECTION OUTPUT ;
    USE SIGNAL ;
    PORT
      LAYER M4 ;
        RECT  0 64.176 0.084 64.2 ;
    END
  END q[311]
  PIN q[312]
    DIRECTION OUTPUT ;
    USE SIGNAL ;
    PORT
      LAYER M4 ;
        RECT  0 64.368 0.084 64.392 ;
    END
  END q[312]
  PIN q[313]
    DIRECTION OUTPUT ;
    USE SIGNAL ;
    PORT
      LAYER M4 ;
        RECT  0 64.56 0.084 64.584 ;
    END
  END q[313]
  PIN q[314]
    DIRECTION OUTPUT ;
    USE SIGNAL ;
    PORT
      LAYER M4 ;
        RECT  0 64.752 0.084 64.776 ;
    END
  END q[314]
  PIN q[315]
    DIRECTION OUTPUT ;
    USE SIGNAL ;
    PORT
      LAYER M4 ;
        RECT  0 64.944 0.084 64.968 ;
    END
  END q[315]
  PIN q[316]
    DIRECTION OUTPUT ;
    USE SIGNAL ;
    PORT
      LAYER M4 ;
        RECT  0 65.136 0.084 65.16 ;
    END
  END q[316]
  PIN q[317]
    DIRECTION OUTPUT ;
    USE SIGNAL ;
    PORT
      LAYER M4 ;
        RECT  0 65.328 0.084 65.352 ;
    END
  END q[317]
  PIN q[318]
    DIRECTION OUTPUT ;
    USE SIGNAL ;
    PORT
      LAYER M4 ;
        RECT  0 65.52 0.084 65.544 ;
    END
  END q[318]
  PIN q[319]
    DIRECTION OUTPUT ;
    USE SIGNAL ;
    PORT
      LAYER M4 ;
        RECT  0 65.712 0.084 65.736 ;
    END
  END q[319]
  PIN q[31]
    DIRECTION OUTPUT ;
    USE SIGNAL ;
    PORT
      LAYER M4 ;
        RECT  0 8.496 0.084 8.52 ;
    END
  END q[31]
  PIN q[320]
    DIRECTION OUTPUT ;
    USE SIGNAL ;
    PORT
      LAYER M4 ;
        RECT  0 65.904 0.084 65.928 ;
    END
  END q[320]
  PIN q[321]
    DIRECTION OUTPUT ;
    USE SIGNAL ;
    PORT
      LAYER M4 ;
        RECT  0 66.096 0.084 66.12 ;
    END
  END q[321]
  PIN q[322]
    DIRECTION OUTPUT ;
    USE SIGNAL ;
    PORT
      LAYER M4 ;
        RECT  0 66.288 0.084 66.312 ;
    END
  END q[322]
  PIN q[323]
    DIRECTION OUTPUT ;
    USE SIGNAL ;
    PORT
      LAYER M4 ;
        RECT  0 66.672 0.084 66.696 ;
    END
  END q[323]
  PIN q[324]
    DIRECTION OUTPUT ;
    USE SIGNAL ;
    PORT
      LAYER M4 ;
        RECT  0 66.48 0.084 66.504 ;
    END
  END q[324]
  PIN q[325]
    DIRECTION OUTPUT ;
    USE SIGNAL ;
    PORT
      LAYER M4 ;
        RECT  0 66.864 0.084 66.888 ;
    END
  END q[325]
  PIN q[326]
    DIRECTION OUTPUT ;
    USE SIGNAL ;
    PORT
      LAYER M4 ;
        RECT  0 67.056 0.084 67.08 ;
    END
  END q[326]
  PIN q[327]
    DIRECTION OUTPUT ;
    USE SIGNAL ;
    PORT
      LAYER M4 ;
        RECT  0 67.248 0.084 67.272 ;
    END
  END q[327]
  PIN q[328]
    DIRECTION OUTPUT ;
    USE SIGNAL ;
    PORT
      LAYER M4 ;
        RECT  0 67.44 0.084 67.464 ;
    END
  END q[328]
  PIN q[329]
    DIRECTION OUTPUT ;
    USE SIGNAL ;
    PORT
      LAYER M4 ;
        RECT  0 67.632 0.084 67.656 ;
    END
  END q[329]
  PIN q[32]
    DIRECTION OUTPUT ;
    USE SIGNAL ;
    PORT
      LAYER M4 ;
        RECT  0 8.688 0.084 8.712 ;
    END
  END q[32]
  PIN q[330]
    DIRECTION OUTPUT ;
    USE SIGNAL ;
    PORT
      LAYER M4 ;
        RECT  0 67.824 0.084 67.848 ;
    END
  END q[330]
  PIN q[331]
    DIRECTION OUTPUT ;
    USE SIGNAL ;
    PORT
      LAYER M4 ;
        RECT  0 68.016 0.084 68.04 ;
    END
  END q[331]
  PIN q[332]
    DIRECTION OUTPUT ;
    USE SIGNAL ;
    PORT
      LAYER M4 ;
        RECT  0 68.208 0.084 68.232 ;
    END
  END q[332]
  PIN q[333]
    DIRECTION OUTPUT ;
    USE SIGNAL ;
    PORT
      LAYER M4 ;
        RECT  0 68.4 0.084 68.424 ;
    END
  END q[333]
  PIN q[334]
    DIRECTION OUTPUT ;
    USE SIGNAL ;
    PORT
      LAYER M4 ;
        RECT  0 68.592 0.084 68.616 ;
    END
  END q[334]
  PIN q[335]
    DIRECTION OUTPUT ;
    USE SIGNAL ;
    PORT
      LAYER M4 ;
        RECT  0 68.784 0.084 68.808 ;
    END
  END q[335]
  PIN q[336]
    DIRECTION OUTPUT ;
    USE SIGNAL ;
    PORT
      LAYER M4 ;
        RECT  0 68.976 0.084 69 ;
    END
  END q[336]
  PIN q[337]
    DIRECTION OUTPUT ;
    USE SIGNAL ;
    PORT
      LAYER M4 ;
        RECT  0 69.168 0.084 69.192 ;
    END
  END q[337]
  PIN q[338]
    DIRECTION OUTPUT ;
    USE SIGNAL ;
    PORT
      LAYER M4 ;
        RECT  0 69.36 0.084 69.384 ;
    END
  END q[338]
  PIN q[339]
    DIRECTION OUTPUT ;
    USE SIGNAL ;
    PORT
      LAYER M4 ;
        RECT  0 69.552 0.084 69.576 ;
    END
  END q[339]
  PIN q[33]
    DIRECTION OUTPUT ;
    USE SIGNAL ;
    PORT
      LAYER M4 ;
        RECT  0 8.88 0.084 8.904 ;
    END
  END q[33]
  PIN q[340]
    DIRECTION OUTPUT ;
    USE SIGNAL ;
    PORT
      LAYER M4 ;
        RECT  0 69.744 0.084 69.768 ;
    END
  END q[340]
  PIN q[341]
    DIRECTION OUTPUT ;
    USE SIGNAL ;
    PORT
      LAYER M4 ;
        RECT  0 69.936 0.084 69.96 ;
    END
  END q[341]
  PIN q[342]
    DIRECTION OUTPUT ;
    USE SIGNAL ;
    PORT
      LAYER M4 ;
        RECT  0 70.128 0.084 70.152 ;
    END
  END q[342]
  PIN q[343]
    DIRECTION OUTPUT ;
    USE SIGNAL ;
    PORT
      LAYER M4 ;
        RECT  0 70.512 0.084 70.536 ;
    END
  END q[343]
  PIN q[344]
    DIRECTION OUTPUT ;
    USE SIGNAL ;
    PORT
      LAYER M4 ;
        RECT  0 70.32 0.084 70.344 ;
    END
  END q[344]
  PIN q[345]
    DIRECTION OUTPUT ;
    USE SIGNAL ;
    PORT
      LAYER M4 ;
        RECT  0 70.704 0.084 70.728 ;
    END
  END q[345]
  PIN q[346]
    DIRECTION OUTPUT ;
    USE SIGNAL ;
    PORT
      LAYER M4 ;
        RECT  0 70.896 0.084 70.92 ;
    END
  END q[346]
  PIN q[347]
    DIRECTION OUTPUT ;
    USE SIGNAL ;
    PORT
      LAYER M4 ;
        RECT  0 71.088 0.084 71.112 ;
    END
  END q[347]
  PIN q[348]
    DIRECTION OUTPUT ;
    USE SIGNAL ;
    PORT
      LAYER M4 ;
        RECT  0 71.28 0.084 71.304 ;
    END
  END q[348]
  PIN q[349]
    DIRECTION OUTPUT ;
    USE SIGNAL ;
    PORT
      LAYER M4 ;
        RECT  0 71.472 0.084 71.496 ;
    END
  END q[349]
  PIN q[34]
    DIRECTION OUTPUT ;
    USE SIGNAL ;
    PORT
      LAYER M4 ;
        RECT  0 9.264 0.084 9.288 ;
    END
  END q[34]
  PIN q[350]
    DIRECTION OUTPUT ;
    USE SIGNAL ;
    PORT
      LAYER M4 ;
        RECT  0 71.664 0.084 71.688 ;
    END
  END q[350]
  PIN q[351]
    DIRECTION OUTPUT ;
    USE SIGNAL ;
    PORT
      LAYER M4 ;
        RECT  0 71.856 0.084 71.88 ;
    END
  END q[351]
  PIN q[352]
    DIRECTION OUTPUT ;
    USE SIGNAL ;
    PORT
      LAYER M4 ;
        RECT  0 72.048 0.084 72.072 ;
    END
  END q[352]
  PIN q[353]
    DIRECTION OUTPUT ;
    USE SIGNAL ;
    PORT
      LAYER M4 ;
        RECT  0 72.24 0.084 72.264 ;
    END
  END q[353]
  PIN q[354]
    DIRECTION OUTPUT ;
    USE SIGNAL ;
    PORT
      LAYER M4 ;
        RECT  0 72.432 0.084 72.456 ;
    END
  END q[354]
  PIN q[355]
    DIRECTION OUTPUT ;
    USE SIGNAL ;
    PORT
      LAYER M4 ;
        RECT  0 72.624 0.084 72.648 ;
    END
  END q[355]
  PIN q[356]
    DIRECTION OUTPUT ;
    USE SIGNAL ;
    PORT
      LAYER M4 ;
        RECT  0 72.816 0.084 72.84 ;
    END
  END q[356]
  PIN q[357]
    DIRECTION OUTPUT ;
    USE SIGNAL ;
    PORT
      LAYER M4 ;
        RECT  0 73.008 0.084 73.032 ;
    END
  END q[357]
  PIN q[358]
    DIRECTION OUTPUT ;
    USE SIGNAL ;
    PORT
      LAYER M4 ;
        RECT  0 73.2 0.084 73.224 ;
    END
  END q[358]
  PIN q[359]
    DIRECTION OUTPUT ;
    USE SIGNAL ;
    PORT
      LAYER M4 ;
        RECT  0 73.392 0.084 73.416 ;
    END
  END q[359]
  PIN q[35]
    DIRECTION OUTPUT ;
    USE SIGNAL ;
    PORT
      LAYER M4 ;
        RECT  0 9.072 0.084 9.096 ;
    END
  END q[35]
  PIN q[360]
    DIRECTION OUTPUT ;
    USE SIGNAL ;
    PORT
      LAYER M4 ;
        RECT  0 73.584 0.084 73.608 ;
    END
  END q[360]
  PIN q[361]
    DIRECTION OUTPUT ;
    USE SIGNAL ;
    PORT
      LAYER M4 ;
        RECT  0 73.776 0.084 73.8 ;
    END
  END q[361]
  PIN q[362]
    DIRECTION OUTPUT ;
    USE SIGNAL ;
    PORT
      LAYER M4 ;
        RECT  0 73.968 0.084 73.992 ;
    END
  END q[362]
  PIN q[363]
    DIRECTION OUTPUT ;
    USE SIGNAL ;
    PORT
      LAYER M4 ;
        RECT  0 74.352 0.084 74.376 ;
    END
  END q[363]
  PIN q[364]
    DIRECTION OUTPUT ;
    USE SIGNAL ;
    PORT
      LAYER M4 ;
        RECT  0 74.16 0.084 74.184 ;
    END
  END q[364]
  PIN q[365]
    DIRECTION OUTPUT ;
    USE SIGNAL ;
    PORT
      LAYER M4 ;
        RECT  0 74.736 0.084 74.76 ;
    END
  END q[365]
  PIN q[366]
    DIRECTION OUTPUT ;
    USE SIGNAL ;
    PORT
      LAYER M4 ;
        RECT  0 74.544 0.084 74.568 ;
    END
  END q[366]
  PIN q[367]
    DIRECTION OUTPUT ;
    USE SIGNAL ;
    PORT
      LAYER M4 ;
        RECT  0 74.928 0.084 74.952 ;
    END
  END q[367]
  PIN q[368]
    DIRECTION OUTPUT ;
    USE SIGNAL ;
    PORT
      LAYER M4 ;
        RECT  0 75.12 0.084 75.144 ;
    END
  END q[368]
  PIN q[369]
    DIRECTION OUTPUT ;
    USE SIGNAL ;
    PORT
      LAYER M4 ;
        RECT  0 75.312 0.084 75.336 ;
    END
  END q[369]
  PIN q[36]
    DIRECTION OUTPUT ;
    USE SIGNAL ;
    PORT
      LAYER M4 ;
        RECT  0 9.648 0.084 9.672 ;
    END
  END q[36]
  PIN q[370]
    DIRECTION OUTPUT ;
    USE SIGNAL ;
    PORT
      LAYER M4 ;
        RECT  0 75.504 0.084 75.528 ;
    END
  END q[370]
  PIN q[371]
    DIRECTION OUTPUT ;
    USE SIGNAL ;
    PORT
      LAYER M4 ;
        RECT  0 75.696 0.084 75.72 ;
    END
  END q[371]
  PIN q[372]
    DIRECTION OUTPUT ;
    USE SIGNAL ;
    PORT
      LAYER M4 ;
        RECT  0 75.888 0.084 75.912 ;
    END
  END q[372]
  PIN q[373]
    DIRECTION OUTPUT ;
    USE SIGNAL ;
    PORT
      LAYER M4 ;
        RECT  0 76.08 0.084 76.104 ;
    END
  END q[373]
  PIN q[374]
    DIRECTION OUTPUT ;
    USE SIGNAL ;
    PORT
      LAYER M4 ;
        RECT  0 76.272 0.084 76.296 ;
    END
  END q[374]
  PIN q[375]
    DIRECTION OUTPUT ;
    USE SIGNAL ;
    PORT
      LAYER M4 ;
        RECT  0 76.464 0.084 76.488 ;
    END
  END q[375]
  PIN q[376]
    DIRECTION OUTPUT ;
    USE SIGNAL ;
    PORT
      LAYER M4 ;
        RECT  0 76.656 0.084 76.68 ;
    END
  END q[376]
  PIN q[377]
    DIRECTION OUTPUT ;
    USE SIGNAL ;
    PORT
      LAYER M4 ;
        RECT  0 76.848 0.084 76.872 ;
    END
  END q[377]
  PIN q[378]
    DIRECTION OUTPUT ;
    USE SIGNAL ;
    PORT
      LAYER M4 ;
        RECT  0 77.04 0.084 77.064 ;
    END
  END q[378]
  PIN q[379]
    DIRECTION OUTPUT ;
    USE SIGNAL ;
    PORT
      LAYER M4 ;
        RECT  0 77.232 0.084 77.256 ;
    END
  END q[379]
  PIN q[37]
    DIRECTION OUTPUT ;
    USE SIGNAL ;
    PORT
      LAYER M4 ;
        RECT  0 9.456 0.084 9.48 ;
    END
  END q[37]
  PIN q[380]
    DIRECTION OUTPUT ;
    USE SIGNAL ;
    PORT
      LAYER M4 ;
        RECT  0 77.424 0.084 77.448 ;
    END
  END q[380]
  PIN q[381]
    DIRECTION OUTPUT ;
    USE SIGNAL ;
    PORT
      LAYER M4 ;
        RECT  0 77.616 0.084 77.64 ;
    END
  END q[381]
  PIN q[382]
    DIRECTION OUTPUT ;
    USE SIGNAL ;
    PORT
      LAYER M4 ;
        RECT  0 77.808 0.084 77.832 ;
    END
  END q[382]
  PIN q[383]
    DIRECTION OUTPUT ;
    USE SIGNAL ;
    PORT
      LAYER M4 ;
        RECT  0 78 0.084 78.024 ;
    END
  END q[383]
  PIN q[384]
    DIRECTION OUTPUT ;
    USE SIGNAL ;
    PORT
      LAYER M4 ;
        RECT  0 78.192 0.084 78.216 ;
    END
  END q[384]
  PIN q[385]
    DIRECTION OUTPUT ;
    USE SIGNAL ;
    PORT
      LAYER M4 ;
        RECT  0 78.576 0.084 78.6 ;
    END
  END q[385]
  PIN q[386]
    DIRECTION OUTPUT ;
    USE SIGNAL ;
    PORT
      LAYER M4 ;
        RECT  0 78.384 0.084 78.408 ;
    END
  END q[386]
  PIN q[387]
    DIRECTION OUTPUT ;
    USE SIGNAL ;
    PORT
      LAYER M4 ;
        RECT  0 78.768 0.084 78.792 ;
    END
  END q[387]
  PIN q[388]
    DIRECTION OUTPUT ;
    USE SIGNAL ;
    PORT
      LAYER M4 ;
        RECT  0 78.96 0.084 78.984 ;
    END
  END q[388]
  PIN q[389]
    DIRECTION OUTPUT ;
    USE SIGNAL ;
    PORT
      LAYER M4 ;
        RECT  0 79.152 0.084 79.176 ;
    END
  END q[389]
  PIN q[38]
    DIRECTION OUTPUT ;
    USE SIGNAL ;
    PORT
      LAYER M4 ;
        RECT  0 9.84 0.084 9.864 ;
    END
  END q[38]
  PIN q[390]
    DIRECTION OUTPUT ;
    USE SIGNAL ;
    PORT
      LAYER M4 ;
        RECT  0 79.344 0.084 79.368 ;
    END
  END q[390]
  PIN q[391]
    DIRECTION OUTPUT ;
    USE SIGNAL ;
    PORT
      LAYER M4 ;
        RECT  0 79.536 0.084 79.56 ;
    END
  END q[391]
  PIN q[392]
    DIRECTION OUTPUT ;
    USE SIGNAL ;
    PORT
      LAYER M4 ;
        RECT  0 79.728 0.084 79.752 ;
    END
  END q[392]
  PIN q[393]
    DIRECTION OUTPUT ;
    USE SIGNAL ;
    PORT
      LAYER M4 ;
        RECT  0 79.92 0.084 79.944 ;
    END
  END q[393]
  PIN q[394]
    DIRECTION OUTPUT ;
    USE SIGNAL ;
    PORT
      LAYER M4 ;
        RECT  0 80.112 0.084 80.136 ;
    END
  END q[394]
  PIN q[395]
    DIRECTION OUTPUT ;
    USE SIGNAL ;
    PORT
      LAYER M4 ;
        RECT  0 80.304 0.084 80.328 ;
    END
  END q[395]
  PIN q[396]
    DIRECTION OUTPUT ;
    USE SIGNAL ;
    PORT
      LAYER M4 ;
        RECT  0 80.496 0.084 80.52 ;
    END
  END q[396]
  PIN q[397]
    DIRECTION OUTPUT ;
    USE SIGNAL ;
    PORT
      LAYER M4 ;
        RECT  0 80.688 0.084 80.712 ;
    END
  END q[397]
  PIN q[398]
    DIRECTION OUTPUT ;
    USE SIGNAL ;
    PORT
      LAYER M4 ;
        RECT  0 80.88 0.084 80.904 ;
    END
  END q[398]
  PIN q[399]
    DIRECTION OUTPUT ;
    USE SIGNAL ;
    PORT
      LAYER M4 ;
        RECT  0 81.072 0.084 81.096 ;
    END
  END q[399]
  PIN q[39]
    DIRECTION OUTPUT ;
    USE SIGNAL ;
    PORT
      LAYER M4 ;
        RECT  0 10.032 0.084 10.056 ;
    END
  END q[39]
  PIN q[3]
    DIRECTION OUTPUT ;
    USE SIGNAL ;
    PORT
      LAYER M4 ;
        RECT  0 3.12 0.084 3.144 ;
    END
  END q[3]
  PIN q[400]
    DIRECTION OUTPUT ;
    USE SIGNAL ;
    PORT
      LAYER M4 ;
        RECT  0 81.264 0.084 81.288 ;
    END
  END q[400]
  PIN q[401]
    DIRECTION OUTPUT ;
    USE SIGNAL ;
    PORT
      LAYER M4 ;
        RECT  0 81.456 0.084 81.48 ;
    END
  END q[401]
  PIN q[402]
    DIRECTION OUTPUT ;
    USE SIGNAL ;
    PORT
      LAYER M4 ;
        RECT  0 81.648 0.084 81.672 ;
    END
  END q[402]
  PIN q[403]
    DIRECTION OUTPUT ;
    USE SIGNAL ;
    PORT
      LAYER M4 ;
        RECT  0 81.84 0.084 81.864 ;
    END
  END q[403]
  PIN q[404]
    DIRECTION OUTPUT ;
    USE SIGNAL ;
    PORT
      LAYER M4 ;
        RECT  0 82.032 0.084 82.056 ;
    END
  END q[404]
  PIN q[405]
    DIRECTION OUTPUT ;
    USE SIGNAL ;
    PORT
      LAYER M4 ;
        RECT  0 82.608 0.084 82.632 ;
    END
  END q[405]
  PIN q[406]
    DIRECTION OUTPUT ;
    USE SIGNAL ;
    PORT
      LAYER M4 ;
        RECT  0 82.224 0.084 82.248 ;
    END
  END q[406]
  PIN q[407]
    DIRECTION OUTPUT ;
    USE SIGNAL ;
    PORT
      LAYER M4 ;
        RECT  0 82.8 0.084 82.824 ;
    END
  END q[407]
  PIN q[408]
    DIRECTION OUTPUT ;
    USE SIGNAL ;
    PORT
      LAYER M4 ;
        RECT  0 82.416 0.084 82.44 ;
    END
  END q[408]
  PIN q[409]
    DIRECTION OUTPUT ;
    USE SIGNAL ;
    PORT
      LAYER M4 ;
        RECT  0 82.992 0.084 83.016 ;
    END
  END q[409]
  PIN q[40]
    DIRECTION OUTPUT ;
    USE SIGNAL ;
    PORT
      LAYER M4 ;
        RECT  0 10.224 0.084 10.248 ;
    END
  END q[40]
  PIN q[410]
    DIRECTION OUTPUT ;
    USE SIGNAL ;
    PORT
      LAYER M4 ;
        RECT  0 83.184 0.084 83.208 ;
    END
  END q[410]
  PIN q[411]
    DIRECTION OUTPUT ;
    USE SIGNAL ;
    PORT
      LAYER M4 ;
        RECT  0 83.376 0.084 83.4 ;
    END
  END q[411]
  PIN q[412]
    DIRECTION OUTPUT ;
    USE SIGNAL ;
    PORT
      LAYER M4 ;
        RECT  0 83.568 0.084 83.592 ;
    END
  END q[412]
  PIN q[413]
    DIRECTION OUTPUT ;
    USE SIGNAL ;
    PORT
      LAYER M4 ;
        RECT  0 83.76 0.084 83.784 ;
    END
  END q[413]
  PIN q[414]
    DIRECTION OUTPUT ;
    USE SIGNAL ;
    PORT
      LAYER M4 ;
        RECT  0 83.952 0.084 83.976 ;
    END
  END q[414]
  PIN q[415]
    DIRECTION OUTPUT ;
    USE SIGNAL ;
    PORT
      LAYER M4 ;
        RECT  0 84.144 0.084 84.168 ;
    END
  END q[415]
  PIN q[416]
    DIRECTION OUTPUT ;
    USE SIGNAL ;
    PORT
      LAYER M4 ;
        RECT  0 84.336 0.084 84.36 ;
    END
  END q[416]
  PIN q[417]
    DIRECTION OUTPUT ;
    USE SIGNAL ;
    PORT
      LAYER M4 ;
        RECT  0 84.528 0.084 84.552 ;
    END
  END q[417]
  PIN q[418]
    DIRECTION OUTPUT ;
    USE SIGNAL ;
    PORT
      LAYER M4 ;
        RECT  0 84.72 0.084 84.744 ;
    END
  END q[418]
  PIN q[419]
    DIRECTION OUTPUT ;
    USE SIGNAL ;
    PORT
      LAYER M4 ;
        RECT  0 84.912 0.084 84.936 ;
    END
  END q[419]
  PIN q[41]
    DIRECTION OUTPUT ;
    USE SIGNAL ;
    PORT
      LAYER M4 ;
        RECT  0 10.416 0.084 10.44 ;
    END
  END q[41]
  PIN q[420]
    DIRECTION OUTPUT ;
    USE SIGNAL ;
    PORT
      LAYER M4 ;
        RECT  0 85.104 0.084 85.128 ;
    END
  END q[420]
  PIN q[421]
    DIRECTION OUTPUT ;
    USE SIGNAL ;
    PORT
      LAYER M4 ;
        RECT  0 85.296 0.084 85.32 ;
    END
  END q[421]
  PIN q[422]
    DIRECTION OUTPUT ;
    USE SIGNAL ;
    PORT
      LAYER M4 ;
        RECT  0 85.488 0.084 85.512 ;
    END
  END q[422]
  PIN q[423]
    DIRECTION OUTPUT ;
    USE SIGNAL ;
    PORT
      LAYER M4 ;
        RECT  0 85.68 0.084 85.704 ;
    END
  END q[423]
  PIN q[424]
    DIRECTION OUTPUT ;
    USE SIGNAL ;
    PORT
      LAYER M4 ;
        RECT  0 85.872 0.084 85.896 ;
    END
  END q[424]
  PIN q[425]
    DIRECTION OUTPUT ;
    USE SIGNAL ;
    PORT
      LAYER M4 ;
        RECT  0 86.448 0.084 86.472 ;
    END
  END q[425]
  PIN q[426]
    DIRECTION OUTPUT ;
    USE SIGNAL ;
    PORT
      LAYER M4 ;
        RECT  0 86.064 0.084 86.088 ;
    END
  END q[426]
  PIN q[427]
    DIRECTION OUTPUT ;
    USE SIGNAL ;
    PORT
      LAYER M4 ;
        RECT  0 86.64 0.084 86.664 ;
    END
  END q[427]
  PIN q[428]
    DIRECTION OUTPUT ;
    USE SIGNAL ;
    PORT
      LAYER M4 ;
        RECT  0 86.256 0.084 86.28 ;
    END
  END q[428]
  PIN q[429]
    DIRECTION OUTPUT ;
    USE SIGNAL ;
    PORT
      LAYER M4 ;
        RECT  0 86.832 0.084 86.856 ;
    END
  END q[429]
  PIN q[42]
    DIRECTION OUTPUT ;
    USE SIGNAL ;
    PORT
      LAYER M4 ;
        RECT  0 10.608 0.084 10.632 ;
    END
  END q[42]
  PIN q[430]
    DIRECTION OUTPUT ;
    USE SIGNAL ;
    PORT
      LAYER M4 ;
        RECT  0 87.024 0.084 87.048 ;
    END
  END q[430]
  PIN q[431]
    DIRECTION OUTPUT ;
    USE SIGNAL ;
    PORT
      LAYER M4 ;
        RECT  0 87.216 0.084 87.24 ;
    END
  END q[431]
  PIN q[432]
    DIRECTION OUTPUT ;
    USE SIGNAL ;
    PORT
      LAYER M4 ;
        RECT  0 87.408 0.084 87.432 ;
    END
  END q[432]
  PIN q[433]
    DIRECTION OUTPUT ;
    USE SIGNAL ;
    PORT
      LAYER M4 ;
        RECT  0 87.6 0.084 87.624 ;
    END
  END q[433]
  PIN q[434]
    DIRECTION OUTPUT ;
    USE SIGNAL ;
    PORT
      LAYER M4 ;
        RECT  0 87.792 0.084 87.816 ;
    END
  END q[434]
  PIN q[435]
    DIRECTION OUTPUT ;
    USE SIGNAL ;
    PORT
      LAYER M4 ;
        RECT  0 87.984 0.084 88.008 ;
    END
  END q[435]
  PIN q[436]
    DIRECTION OUTPUT ;
    USE SIGNAL ;
    PORT
      LAYER M4 ;
        RECT  0 88.176 0.084 88.2 ;
    END
  END q[436]
  PIN q[437]
    DIRECTION OUTPUT ;
    USE SIGNAL ;
    PORT
      LAYER M4 ;
        RECT  0 88.368 0.084 88.392 ;
    END
  END q[437]
  PIN q[438]
    DIRECTION OUTPUT ;
    USE SIGNAL ;
    PORT
      LAYER M4 ;
        RECT  0 88.56 0.084 88.584 ;
    END
  END q[438]
  PIN q[439]
    DIRECTION OUTPUT ;
    USE SIGNAL ;
    PORT
      LAYER M4 ;
        RECT  0 88.944 0.084 88.968 ;
    END
  END q[439]
  PIN q[43]
    DIRECTION OUTPUT ;
    USE SIGNAL ;
    PORT
      LAYER M4 ;
        RECT  0 10.8 0.084 10.824 ;
    END
  END q[43]
  PIN q[440]
    DIRECTION OUTPUT ;
    USE SIGNAL ;
    PORT
      LAYER M4 ;
        RECT  0 88.752 0.084 88.776 ;
    END
  END q[440]
  PIN q[441]
    DIRECTION OUTPUT ;
    USE SIGNAL ;
    PORT
      LAYER M4 ;
        RECT  0 89.136 0.084 89.16 ;
    END
  END q[441]
  PIN q[442]
    DIRECTION OUTPUT ;
    USE SIGNAL ;
    PORT
      LAYER M4 ;
        RECT  0 89.328 0.084 89.352 ;
    END
  END q[442]
  PIN q[443]
    DIRECTION OUTPUT ;
    USE SIGNAL ;
    PORT
      LAYER M4 ;
        RECT  0 89.52 0.084 89.544 ;
    END
  END q[443]
  PIN q[444]
    DIRECTION OUTPUT ;
    USE SIGNAL ;
    PORT
      LAYER M4 ;
        RECT  0 89.712 0.084 89.736 ;
    END
  END q[444]
  PIN q[445]
    DIRECTION OUTPUT ;
    USE SIGNAL ;
    PORT
      LAYER M4 ;
        RECT  0 89.904 0.084 89.928 ;
    END
  END q[445]
  PIN q[446]
    DIRECTION OUTPUT ;
    USE SIGNAL ;
    PORT
      LAYER M4 ;
        RECT  0 90.096 0.084 90.12 ;
    END
  END q[446]
  PIN q[447]
    DIRECTION OUTPUT ;
    USE SIGNAL ;
    PORT
      LAYER M4 ;
        RECT  0 90.48 0.084 90.504 ;
    END
  END q[447]
  PIN q[448]
    DIRECTION OUTPUT ;
    USE SIGNAL ;
    PORT
      LAYER M4 ;
        RECT  0 90.288 0.084 90.312 ;
    END
  END q[448]
  PIN q[449]
    DIRECTION OUTPUT ;
    USE SIGNAL ;
    PORT
      LAYER M4 ;
        RECT  0 90.672 0.084 90.696 ;
    END
  END q[449]
  PIN q[44]
    DIRECTION OUTPUT ;
    USE SIGNAL ;
    PORT
      LAYER M4 ;
        RECT  0 10.992 0.084 11.016 ;
    END
  END q[44]
  PIN q[450]
    DIRECTION OUTPUT ;
    USE SIGNAL ;
    PORT
      LAYER M4 ;
        RECT  0 90.864 0.084 90.888 ;
    END
  END q[450]
  PIN q[451]
    DIRECTION OUTPUT ;
    USE SIGNAL ;
    PORT
      LAYER M4 ;
        RECT  0 91.248 0.084 91.272 ;
    END
  END q[451]
  PIN q[452]
    DIRECTION OUTPUT ;
    USE SIGNAL ;
    PORT
      LAYER M4 ;
        RECT  0 91.056 0.084 91.08 ;
    END
  END q[452]
  PIN q[453]
    DIRECTION OUTPUT ;
    USE SIGNAL ;
    PORT
      LAYER M4 ;
        RECT  0 91.44 0.084 91.464 ;
    END
  END q[453]
  PIN q[454]
    DIRECTION OUTPUT ;
    USE SIGNAL ;
    PORT
      LAYER M4 ;
        RECT  0 91.632 0.084 91.656 ;
    END
  END q[454]
  PIN q[455]
    DIRECTION OUTPUT ;
    USE SIGNAL ;
    PORT
      LAYER M4 ;
        RECT  0 91.824 0.084 91.848 ;
    END
  END q[455]
  PIN q[456]
    DIRECTION OUTPUT ;
    USE SIGNAL ;
    PORT
      LAYER M4 ;
        RECT  0 92.016 0.084 92.04 ;
    END
  END q[456]
  PIN q[45]
    DIRECTION OUTPUT ;
    USE SIGNAL ;
    PORT
      LAYER M4 ;
        RECT  0 11.184 0.084 11.208 ;
    END
  END q[45]
  PIN q[46]
    DIRECTION OUTPUT ;
    USE SIGNAL ;
    PORT
      LAYER M4 ;
        RECT  0 11.376 0.084 11.4 ;
    END
  END q[46]
  PIN q[47]
    DIRECTION OUTPUT ;
    USE SIGNAL ;
    PORT
      LAYER M4 ;
        RECT  0 11.568 0.084 11.592 ;
    END
  END q[47]
  PIN q[48]
    DIRECTION OUTPUT ;
    USE SIGNAL ;
    PORT
      LAYER M4 ;
        RECT  0 11.76 0.084 11.784 ;
    END
  END q[48]
  PIN q[49]
    DIRECTION OUTPUT ;
    USE SIGNAL ;
    PORT
      LAYER M4 ;
        RECT  0 11.952 0.084 11.976 ;
    END
  END q[49]
  PIN q[4]
    DIRECTION OUTPUT ;
    USE SIGNAL ;
    PORT
      LAYER M4 ;
        RECT  0 3.312 0.084 3.336 ;
    END
  END q[4]
  PIN q[50]
    DIRECTION OUTPUT ;
    USE SIGNAL ;
    PORT
      LAYER M4 ;
        RECT  0 12.144 0.084 12.168 ;
    END
  END q[50]
  PIN q[51]
    DIRECTION OUTPUT ;
    USE SIGNAL ;
    PORT
      LAYER M4 ;
        RECT  0 12.336 0.084 12.36 ;
    END
  END q[51]
  PIN q[52]
    DIRECTION OUTPUT ;
    USE SIGNAL ;
    PORT
      LAYER M4 ;
        RECT  0 12.528 0.084 12.552 ;
    END
  END q[52]
  PIN q[53]
    DIRECTION OUTPUT ;
    USE SIGNAL ;
    PORT
      LAYER M4 ;
        RECT  0 12.72 0.084 12.744 ;
    END
  END q[53]
  PIN q[54]
    DIRECTION OUTPUT ;
    USE SIGNAL ;
    PORT
      LAYER M4 ;
        RECT  0 13.296 0.084 13.32 ;
    END
  END q[54]
  PIN q[55]
    DIRECTION OUTPUT ;
    USE SIGNAL ;
    PORT
      LAYER M4 ;
        RECT  0 12.912 0.084 12.936 ;
    END
  END q[55]
  PIN q[56]
    DIRECTION OUTPUT ;
    USE SIGNAL ;
    PORT
      LAYER M4 ;
        RECT  0 13.488 0.084 13.512 ;
    END
  END q[56]
  PIN q[57]
    DIRECTION OUTPUT ;
    USE SIGNAL ;
    PORT
      LAYER M4 ;
        RECT  0 13.104 0.084 13.128 ;
    END
  END q[57]
  PIN q[58]
    DIRECTION OUTPUT ;
    USE SIGNAL ;
    PORT
      LAYER M4 ;
        RECT  0 13.68 0.084 13.704 ;
    END
  END q[58]
  PIN q[59]
    DIRECTION OUTPUT ;
    USE SIGNAL ;
    PORT
      LAYER M4 ;
        RECT  0 13.872 0.084 13.896 ;
    END
  END q[59]
  PIN q[5]
    DIRECTION OUTPUT ;
    USE SIGNAL ;
    PORT
      LAYER M4 ;
        RECT  0 3.504 0.084 3.528 ;
    END
  END q[5]
  PIN q[60]
    DIRECTION OUTPUT ;
    USE SIGNAL ;
    PORT
      LAYER M4 ;
        RECT  0 14.064 0.084 14.088 ;
    END
  END q[60]
  PIN q[61]
    DIRECTION OUTPUT ;
    USE SIGNAL ;
    PORT
      LAYER M4 ;
        RECT  0 14.256 0.084 14.28 ;
    END
  END q[61]
  PIN q[62]
    DIRECTION OUTPUT ;
    USE SIGNAL ;
    PORT
      LAYER M4 ;
        RECT  0 14.448 0.084 14.472 ;
    END
  END q[62]
  PIN q[63]
    DIRECTION OUTPUT ;
    USE SIGNAL ;
    PORT
      LAYER M4 ;
        RECT  0 14.64 0.084 14.664 ;
    END
  END q[63]
  PIN q[64]
    DIRECTION OUTPUT ;
    USE SIGNAL ;
    PORT
      LAYER M4 ;
        RECT  0 14.832 0.084 14.856 ;
    END
  END q[64]
  PIN q[65]
    DIRECTION OUTPUT ;
    USE SIGNAL ;
    PORT
      LAYER M4 ;
        RECT  0 15.024 0.084 15.048 ;
    END
  END q[65]
  PIN q[66]
    DIRECTION OUTPUT ;
    USE SIGNAL ;
    PORT
      LAYER M4 ;
        RECT  0 15.216 0.084 15.24 ;
    END
  END q[66]
  PIN q[67]
    DIRECTION OUTPUT ;
    USE SIGNAL ;
    PORT
      LAYER M4 ;
        RECT  0 15.408 0.084 15.432 ;
    END
  END q[67]
  PIN q[68]
    DIRECTION OUTPUT ;
    USE SIGNAL ;
    PORT
      LAYER M4 ;
        RECT  0 15.6 0.084 15.624 ;
    END
  END q[68]
  PIN q[69]
    DIRECTION OUTPUT ;
    USE SIGNAL ;
    PORT
      LAYER M4 ;
        RECT  0 15.792 0.084 15.816 ;
    END
  END q[69]
  PIN q[6]
    DIRECTION OUTPUT ;
    USE SIGNAL ;
    PORT
      LAYER M4 ;
        RECT  0 3.696 0.084 3.72 ;
    END
  END q[6]
  PIN q[70]
    DIRECTION OUTPUT ;
    USE SIGNAL ;
    PORT
      LAYER M4 ;
        RECT  0 15.984 0.084 16.008 ;
    END
  END q[70]
  PIN q[71]
    DIRECTION OUTPUT ;
    USE SIGNAL ;
    PORT
      LAYER M4 ;
        RECT  0 16.176 0.084 16.2 ;
    END
  END q[71]
  PIN q[72]
    DIRECTION OUTPUT ;
    USE SIGNAL ;
    PORT
      LAYER M4 ;
        RECT  0 16.368 0.084 16.392 ;
    END
  END q[72]
  PIN q[73]
    DIRECTION OUTPUT ;
    USE SIGNAL ;
    PORT
      LAYER M4 ;
        RECT  0 16.56 0.084 16.584 ;
    END
  END q[73]
  PIN q[74]
    DIRECTION OUTPUT ;
    USE SIGNAL ;
    PORT
      LAYER M4 ;
        RECT  0 16.752 0.084 16.776 ;
    END
  END q[74]
  PIN q[75]
    DIRECTION OUTPUT ;
    USE SIGNAL ;
    PORT
      LAYER M4 ;
        RECT  0 16.944 0.084 16.968 ;
    END
  END q[75]
  PIN q[76]
    DIRECTION OUTPUT ;
    USE SIGNAL ;
    PORT
      LAYER M4 ;
        RECT  0 17.328 0.084 17.352 ;
    END
  END q[76]
  PIN q[77]
    DIRECTION OUTPUT ;
    USE SIGNAL ;
    PORT
      LAYER M4 ;
        RECT  0 17.136 0.084 17.16 ;
    END
  END q[77]
  PIN q[78]
    DIRECTION OUTPUT ;
    USE SIGNAL ;
    PORT
      LAYER M4 ;
        RECT  0 17.52 0.084 17.544 ;
    END
  END q[78]
  PIN q[79]
    DIRECTION OUTPUT ;
    USE SIGNAL ;
    PORT
      LAYER M4 ;
        RECT  0 17.712 0.084 17.736 ;
    END
  END q[79]
  PIN q[7]
    DIRECTION OUTPUT ;
    USE SIGNAL ;
    PORT
      LAYER M4 ;
        RECT  0 3.888 0.084 3.912 ;
    END
  END q[7]
  PIN q[80]
    DIRECTION OUTPUT ;
    USE SIGNAL ;
    PORT
      LAYER M4 ;
        RECT  0 17.904 0.084 17.928 ;
    END
  END q[80]
  PIN q[81]
    DIRECTION OUTPUT ;
    USE SIGNAL ;
    PORT
      LAYER M4 ;
        RECT  0 18.096 0.084 18.12 ;
    END
  END q[81]
  PIN q[82]
    DIRECTION OUTPUT ;
    USE SIGNAL ;
    PORT
      LAYER M4 ;
        RECT  0 18.288 0.084 18.312 ;
    END
  END q[82]
  PIN q[83]
    DIRECTION OUTPUT ;
    USE SIGNAL ;
    PORT
      LAYER M4 ;
        RECT  0 18.48 0.084 18.504 ;
    END
  END q[83]
  PIN q[84]
    DIRECTION OUTPUT ;
    USE SIGNAL ;
    PORT
      LAYER M4 ;
        RECT  0 18.672 0.084 18.696 ;
    END
  END q[84]
  PIN q[85]
    DIRECTION OUTPUT ;
    USE SIGNAL ;
    PORT
      LAYER M4 ;
        RECT  0 18.864 0.084 18.888 ;
    END
  END q[85]
  PIN q[86]
    DIRECTION OUTPUT ;
    USE SIGNAL ;
    PORT
      LAYER M4 ;
        RECT  0 19.056 0.084 19.08 ;
    END
  END q[86]
  PIN q[87]
    DIRECTION OUTPUT ;
    USE SIGNAL ;
    PORT
      LAYER M4 ;
        RECT  0 19.248 0.084 19.272 ;
    END
  END q[87]
  PIN q[88]
    DIRECTION OUTPUT ;
    USE SIGNAL ;
    PORT
      LAYER M4 ;
        RECT  0 19.44 0.084 19.464 ;
    END
  END q[88]
  PIN q[89]
    DIRECTION OUTPUT ;
    USE SIGNAL ;
    PORT
      LAYER M4 ;
        RECT  0 19.632 0.084 19.656 ;
    END
  END q[89]
  PIN q[8]
    DIRECTION OUTPUT ;
    USE SIGNAL ;
    PORT
      LAYER M4 ;
        RECT  0 4.272 0.084 4.296 ;
    END
  END q[8]
  PIN q[90]
    DIRECTION OUTPUT ;
    USE SIGNAL ;
    PORT
      LAYER M4 ;
        RECT  0 19.824 0.084 19.848 ;
    END
  END q[90]
  PIN q[91]
    DIRECTION OUTPUT ;
    USE SIGNAL ;
    PORT
      LAYER M4 ;
        RECT  0 20.016 0.084 20.04 ;
    END
  END q[91]
  PIN q[92]
    DIRECTION OUTPUT ;
    USE SIGNAL ;
    PORT
      LAYER M4 ;
        RECT  0 20.208 0.084 20.232 ;
    END
  END q[92]
  PIN q[93]
    DIRECTION OUTPUT ;
    USE SIGNAL ;
    PORT
      LAYER M4 ;
        RECT  0 20.4 0.084 20.424 ;
    END
  END q[93]
  PIN q[94]
    DIRECTION OUTPUT ;
    USE SIGNAL ;
    PORT
      LAYER M4 ;
        RECT  0 20.592 0.084 20.616 ;
    END
  END q[94]
  PIN q[95]
    DIRECTION OUTPUT ;
    USE SIGNAL ;
    PORT
      LAYER M4 ;
        RECT  0 20.784 0.084 20.808 ;
    END
  END q[95]
  PIN q[96]
    DIRECTION OUTPUT ;
    USE SIGNAL ;
    PORT
      LAYER M4 ;
        RECT  0 21.168 0.084 21.192 ;
    END
  END q[96]
  PIN q[97]
    DIRECTION OUTPUT ;
    USE SIGNAL ;
    PORT
      LAYER M4 ;
        RECT  0 20.976 0.084 21 ;
    END
  END q[97]
  PIN q[98]
    DIRECTION OUTPUT ;
    USE SIGNAL ;
    PORT
      LAYER M4 ;
        RECT  0 21.552 0.084 21.576 ;
    END
  END q[98]
  PIN q[99]
    DIRECTION OUTPUT ;
    USE SIGNAL ;
    PORT
      LAYER M4 ;
        RECT  0 21.36 0.084 21.384 ;
    END
  END q[99]
  PIN q[9]
    DIRECTION OUTPUT ;
    USE SIGNAL ;
    PORT
      LAYER M4 ;
        RECT  0 4.08 0.084 4.104 ;
    END
  END q[9]
  PIN ready
    DIRECTION OUTPUT ;
    USE SIGNAL ;
    PORT
      LAYER M4 ;
        RECT  0 46.704 0.084 46.728 ;
    END
  END ready
  PIN rst_n
    DIRECTION INPUT ;
    USE SIGNAL ;
    PORT
      LAYER M4 ;
        RECT  0 46.512 0.084 46.536 ;
    END
  END rst_n
  PIN strap_k[0]
    DIRECTION INPUT ;
    USE SIGNAL ;
    PORT
      LAYER M4 ;
        RECT  0 47.088 0.084 47.112 ;
    END
  END strap_k[0]
  PIN strap_k[1]
    DIRECTION INPUT ;
    USE SIGNAL ;
    PORT
      LAYER M4 ;
        RECT  0 47.28 0.084 47.304 ;
    END
  END strap_k[1]
  PIN strap_k[2]
    DIRECTION INPUT ;
    USE SIGNAL ;
    PORT
      LAYER M4 ;
        RECT  0 47.472 0.084 47.496 ;
    END
  END strap_k[2]
  PIN strap_k[3]
    DIRECTION INPUT ;
    USE SIGNAL ;
    PORT
      LAYER M4 ;
        RECT  0 47.664 0.084 47.688 ;
    END
  END strap_k[3]
  PIN strap_k[4]
    DIRECTION INPUT ;
    USE SIGNAL ;
    PORT
      LAYER M4 ;
        RECT  0 47.856 0.084 47.88 ;
    END
  END strap_k[4]
  PIN strap_k[5]
    DIRECTION INPUT ;
    USE SIGNAL ;
    PORT
      LAYER M4 ;
        RECT  0 48.048 0.084 48.072 ;
    END
  END strap_k[5]
  PIN t_rst_n
    DIRECTION INPUT ;
    USE SIGNAL ;
    PORT
      LAYER M4 ;
        RECT  43.116 47.28 43.2 47.304 ;
    END
  END t_rst_n
  PIN VDD
    DIRECTION INOUT ;
    USE POWER ;
    PORT
      LAYER M5 ;
        RECT  36.756 4.311 36.876 90.189 ;
        RECT  32.436 4.311 32.556 90.189 ;
        RECT  28.116 4.311 28.236 90.189 ;
        RECT  23.796 4.311 23.916 90.189 ;
        RECT  19.476 4.311 19.596 90.189 ;
        RECT  15.156 4.311 15.276 90.189 ;
        RECT  10.836 4.311 10.956 90.189 ;
        RECT  6.516 4.311 6.636 90.189 ;
    END
  END VDD
  PIN VSS
    DIRECTION INOUT ;
    USE GROUND ;
    PORT
      LAYER M5 ;
        RECT  36.564 4.297 36.684 90.203 ;
        RECT  32.244 4.297 32.364 90.203 ;
        RECT  27.924 4.297 28.044 90.203 ;
        RECT  23.604 4.297 23.724 90.203 ;
        RECT  19.284 4.297 19.404 90.203 ;
        RECT  14.964 4.297 15.084 90.203 ;
        RECT  10.644 4.297 10.764 90.203 ;
        RECT  6.324 4.297 6.444 90.203 ;
    END
  END VSS
  OBS
    LAYER RVTN ;
     RECT  0 2.539 43.2 92.045 ;
    LAYER RVTP ;
     RECT  0 2.539 43.2 92.045 ;
    LAYER M1 ;
     RECT  0 2.539 43.2 92.045 ;
    LAYER M2 ;
     RECT  0 2.539 43.2 92.045 ;
    LAYER M3 ;
     RECT  0 2.539 43.2 92.045 ;
    LAYER M4 ;
     RECT  0 2.539 43.2 92.045 ;
    LAYER M5 ;
     RECT  0 2.539 43.2 92.045 ;
  END
END sle_cland_w457_e
END LIBRARY
